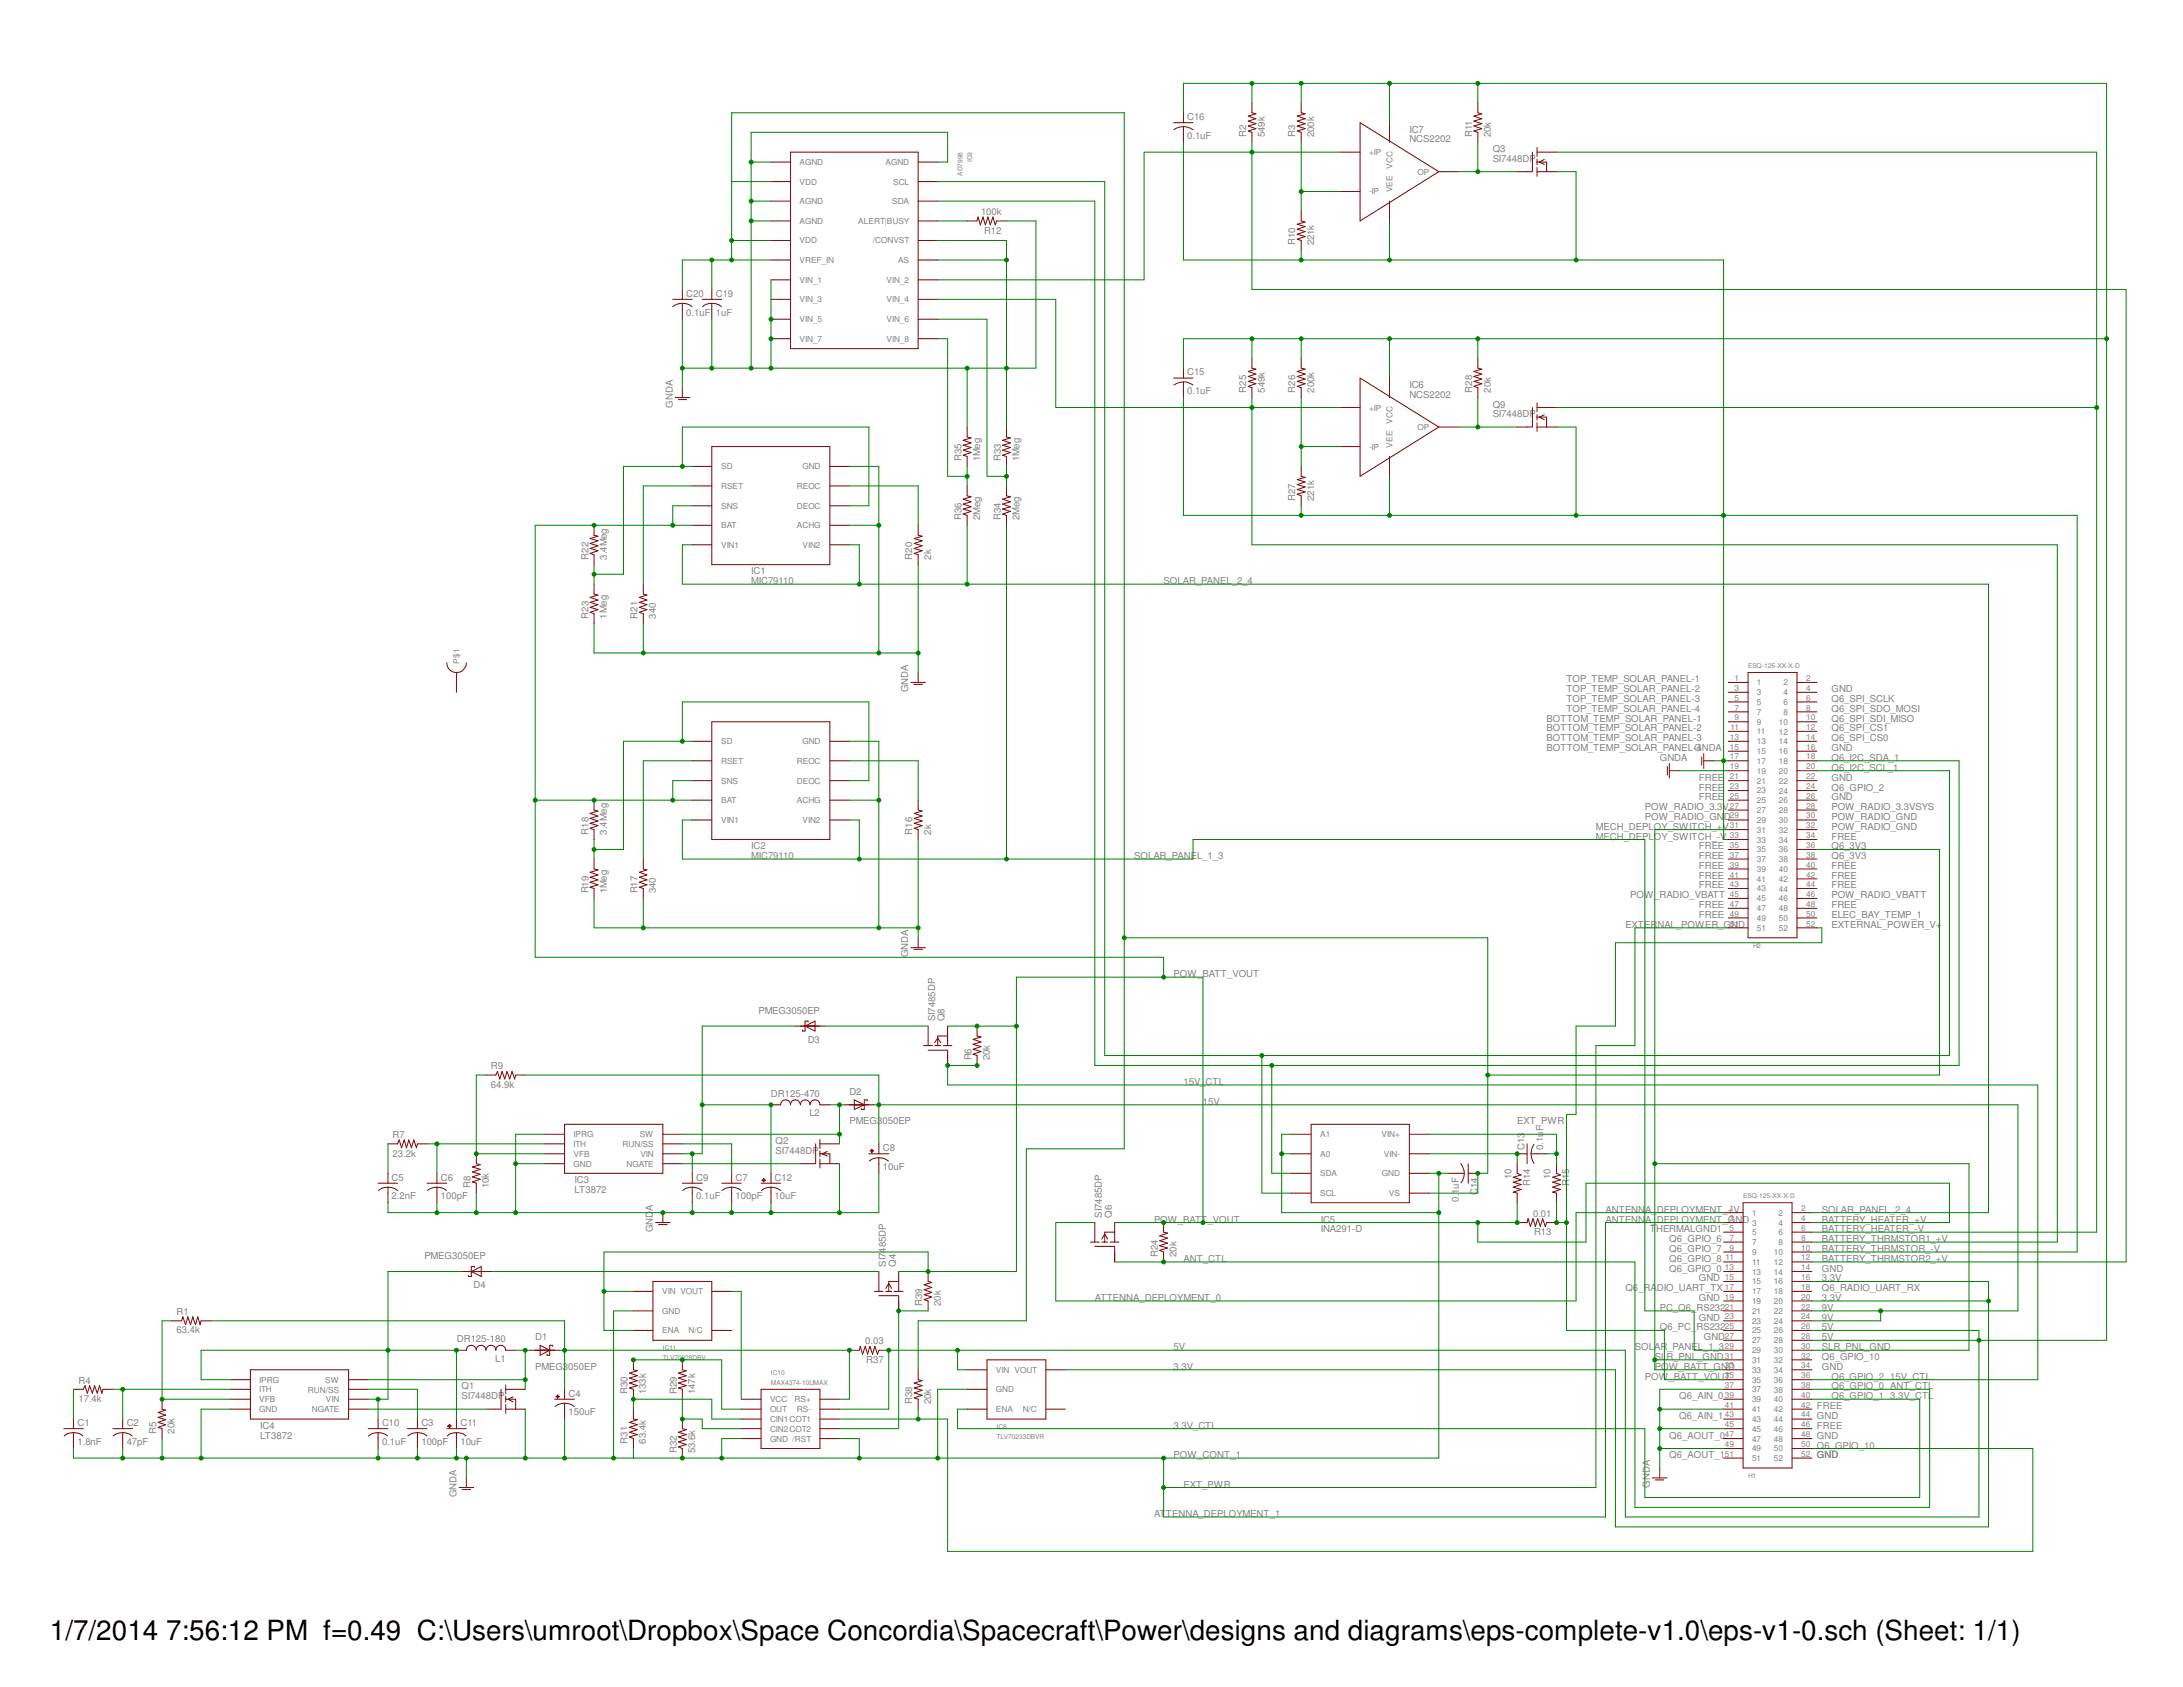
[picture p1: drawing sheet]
<svg xmlns="http://www.w3.org/2000/svg" width="279mm" height="216mm" viewBox="0 0 279 216" stroke-linecap="round" stroke-linejoin="round" font-family="sans-serif">
<defs><g id="words">
<text font-size="3.6" x="6.4" y="209.9">1/7/2014 7:56:12 PM f=0.49 C:\Users\umroot\Dropbox\Space Concordia\Spacecraft\Power\designs and diagrams\eps-complete-v1.0\eps-v1-0.sch (Sheet: 1/1)</text>
<g font-size="1.2" fill="#808080">
<text x="151.9" y="17.8">0.1uF</text>
<text x="151.9" y="15.4">C16</text>
<text x="159.5" y="17.6" transform="rotate(-90 159.5 17.6)">R2</text>
<text x="161.9" y="17.6" transform="rotate(-90 161.9 17.6)">549k</text>
<text x="165.8" y="17.6" transform="rotate(-90 165.8 17.6)">R3</text>
<text x="168.2" y="17.6" transform="rotate(-90 168.2 17.6)">200k</text>
<text x="180.4" y="17">IC7</text>
<text x="188.4" y="17.6" transform="rotate(-90 188.4 17.6)">R11</text>
<text x="190.8" y="17.6" transform="rotate(-90 190.8 17.6)">20k</text>
<text x="180.4" y="18.2">NCS2202</text>
<text x="191.1" y="20.7">SI7448DP</text>
<text x="191.1" y="19.5">Q3</text>
<text x="125.6" y="27.5">100k</text>
<text x="125.9" y="29.9">R12</text>
<text x="165.8" y="31.4" transform="rotate(-90 165.8 31.4)">R10</text>
<text x="168.2" y="31.4" transform="rotate(-90 168.2 31.4)">221k</text>
<text x="87.8" y="40.4">0.1uF 1uF</text>
<text x="87.8" y="38">C20</text>
<text x="91.6" y="38">C19</text>
<text x="86.1" y="52.2" transform="rotate(-90 86.1 52.2)">GNDA</text>
<text x="151.9" y="50.5">0.1uF</text>
<text x="151.9" y="48">C15</text>
<text x="159.5" y="50.2" transform="rotate(-90 159.5 50.2)">R25</text>
<text x="161.9" y="50.2" transform="rotate(-90 161.9 50.2)">549k</text>
<text x="165.8" y="50.2" transform="rotate(-90 165.8 50.2)">R26</text>
<text x="168.2" y="50.2" transform="rotate(-90 168.2 50.2)">200k</text>
<text x="180.4" y="50.9">NCS2202</text>
<text x="180.4" y="49.6">IC6</text>
<text x="188.4" y="50.2" transform="rotate(-90 188.4 50.2)">R28</text>
<text x="190.8" y="50.2" transform="rotate(-90 190.8 50.2)">20k</text>
<text x="191.1" y="53.4">SI7448DP</text>
<text x="191.1" y="52.2">Q9</text>
<text x="123.1" y="59.1" transform="rotate(-90 123.1 59.1)">R35</text>
<text x="125.4" y="59.1" transform="rotate(-90 125.4 59.1)">1Meg</text>
<text x="128.1" y="59.1" transform="rotate(-90 128.1 59.1)">R33</text>
<text x="130.5" y="59.1" transform="rotate(-90 130.5 59.1)">1Meg</text>
<text x="165.8" y="64.1" transform="rotate(-90 165.8 64.1)">R27</text>
<text x="168.2" y="64.1" transform="rotate(-90 168.2 64.1)">221k</text>
<text x="75.3" y="71.6" transform="rotate(-90 75.3 71.6)">R22</text>
<text x="77.7" y="71.6" transform="rotate(-90 77.7 71.6)">3.4Meg</text>
<text x="116.8" y="71.6" transform="rotate(-90 116.8 71.6)">R20</text>
<text x="119.2" y="71.6" transform="rotate(-90 119.2 71.6)">2k</text>
<text x="123.1" y="66.6" transform="rotate(-90 123.1 66.6)">R36</text>
<text x="125.4" y="66.6" transform="rotate(-90 125.4 66.6)">2Meg</text>
<text x="128.1" y="66.6" transform="rotate(-90 128.1 66.6)">R34</text>
<text x="130.5" y="66.6" transform="rotate(-90 130.5 66.6)">2Meg</text>
<text x="96.1" y="74.8">MIC79110</text>
<text x="96.1" y="73.5">IC1</text>
<text x="148.9" y="74.8">SOLAR_PANEL_2_4</text>
<text x="75.3" y="79.2" transform="rotate(-90 75.3 79.2)">R23</text>
<text x="77.7" y="79.2" transform="rotate(-90 77.7 79.2)">1Meg</text>
<text x="81.6" y="79.2" transform="rotate(-90 81.6 79.2)">R21</text>
<text x="83.9" y="79.2" transform="rotate(-90 83.9 79.2)">340</text>
<text x="116.2" y="88.6" transform="rotate(-90 116.2 88.6)">GNDA</text>
<text x="200.5" y="89.8">TOP_TEMP_SOLAR_PANEL-3</text>
<text x="200.5" y="88.6">TOP_TEMP_SOLAR_PANEL-2</text>
<text x="200.5" y="87.3">TOP_TEMP_SOLAR_PANEL-1</text>
<text x="234.4" y="89.8">Q6_SPI_SCLK</text>
<text x="234.4" y="88.6">GND</text>
<text x="198" y="92.4">BOTTOM_TEMP_SOLAR_PANEL-1</text>
<text x="198" y="93.6">BOTTOM_TEMP_SOLAR_PANEL-2</text>
<text x="198" y="94.9">BOTTOM_TEMP_SOLAR_PANEL-3</text>
<text x="200.5" y="91.1">TOP_TEMP_SOLAR_PANEL-4</text>
<text x="234.4" y="91.1">Q6_SPI_SDO_MOSI</text>
<text x="234.4" y="92.4">Q6_SPI_SDI_MISO</text>
<text x="234.4" y="93.6">Q6_SPI_CS1</text>
<text x="234.4" y="94.9">Q6_SPI_CS0</text>
<text x="198" y="96.1">BOTTOM_TEMP_SOLAR_PANEL-4</text>
<text x="212.4" y="97.4">GNDA</text>
<text x="216.8" y="96.1">GNDA</text>
<text x="217.4" y="99.9">FREE</text>
<text x="217.4" y="101.2">FREE</text>
<text x="234.4" y="97.4">Q6_I2C_SDA_1</text>
<text x="234.4" y="96.1">GND</text>
<text x="234.4" y="99.9">GND</text>
<text x="234.4" y="98.6">Q6_I2C_SCL_1</text>
<text x="234.4" y="101.2">Q6_GPIO_2</text>
<text x="75.3" y="106.8" transform="rotate(-90 75.3 106.8)">R18</text>
<text x="77.7" y="106.8" transform="rotate(-90 77.7 106.8)">3.4Meg</text>
<text x="116.8" y="106.8" transform="rotate(-90 116.8 106.8)">R16</text>
<text x="119.2" y="106.8" transform="rotate(-90 119.2 106.8)">2k</text>
<text x="204.3" y="107.4">MECH_DEPLOY_SWITCH_-V</text>
<text x="204.3" y="106.2">MECH_DEPLOY_SWITCH_+V</text>
<text x="210.5" y="103.7">POW_RADIO_3.3V</text>
<text x="210.5" y="104.9">POW_RADIO_GND</text>
<text x="217.4" y="102.4">FREE</text>
<text x="234.4" y="102.4">GND</text>
<text x="234.4" y="103.7">POW_RADIO_3.3VSYS</text>
<text x="234.4" y="104.9">POW_RADIO_GND</text>
<text x="234.4" y="106.2">POW_RADIO_GND</text>
<text x="234.4" y="107.4">FREE</text>
<text x="96.1" y="109.9">MIC79110</text>
<text x="96.1" y="108.7">IC2</text>
<text x="145.2" y="109.9">SOLAR_PANEL_1_3</text>
<text x="217.4" y="108.7">FREE</text>
<text x="217.4" y="109.9">FREE</text>
<text x="217.4" y="111.2">FREE</text>
<text x="217.4" y="112.5">FREE</text>
<text x="217.4" y="113.7">FREE</text>
<text x="234.4" y="108.7">Q6_3V3</text>
<text x="234.4" y="109.9">Q6_3V3</text>
<text x="234.4" y="113.7">FREE</text>
<text x="234.4" y="112.5">FREE</text>
<text x="234.4" y="111.2">FREE</text>
<text x="75.3" y="114.3" transform="rotate(-90 75.3 114.3)">R19</text>
<text x="77.7" y="114.3" transform="rotate(-90 77.7 114.3)">1Meg</text>
<text x="81.6" y="114.3" transform="rotate(-90 81.6 114.3)">R17</text>
<text x="83.9" y="114.3" transform="rotate(-90 83.9 114.3)">340</text>
<text x="208" y="118.7">EXTERNAL_POWER_GND</text>
<text x="208.7" y="115">POW_RADIO_VBATT</text>
<text x="217.4" y="116.2">FREE</text>
<text x="217.4" y="117.5">FREE</text>
<text x="234.4" y="115">POW_RADIO_VBATT</text>
<text x="234.4" y="117.5">ELEC_BAY_TEMP_1</text>
<text x="234.4" y="118.7">EXTERNAL_POWER_V+</text>
<text x="234.4" y="116.2">FREE</text>
<text x="116.2" y="122.5" transform="rotate(-90 116.2 122.5)">GNDA</text>
<text x="150.2" y="125.1">POW_BATT_VOUT</text>
<text x="97.1" y="129.7">PMEG3050EP</text>
<text x="119.7" y="130.7" transform="rotate(-90 119.7 130.7)">SI7485DP</text>
<text x="120.9" y="130.7" transform="rotate(-90 120.9 130.7)">Q8</text>
<text x="62.8" y="136.9">R9</text>
<text x="103.4" y="133.5">D3</text>
<text x="124.3" y="135.7" transform="rotate(-90 124.3 135.7)">R6</text>
<text x="126.7" y="135.7" transform="rotate(-90 126.7 135.7)">20k</text>
<text x="62.8" y="139.2">64.9k</text>
<text x="98.7" y="140.4">DR125-470</text>
<text x="103.6" y="142.9">L2</text>
<text x="108.7" y="143.9">PMEG3050EP</text>
<text x="108.7" y="140.1">D2</text>
<text x="151.5" y="138.9">15V_CTL</text>
<text x="154" y="141.4">15V</text>
<text x="194.2" y="143.9">EXT_PWR</text>
<text x="50.2" y="148">23.2k</text>
<text x="50.2" y="145.7">R7</text>
<text x="99.3" y="147.7">SI7448DP</text>
<text x="99.3" y="146.4">Q2</text>
<text x="113" y="149.7">10uF</text>
<text x="113" y="147.4">C8</text>
<text x="195.1" y="147.2" transform="rotate(-90 195.1 147.2)">C13</text>
<text x="197.5" y="147.2" transform="rotate(-90 197.5 147.2)">0.1uF</text>
<text x="50.1" y="153.5">2.2nF</text>
<text x="50.1" y="151.1">C5</text>
<text x="56.4" y="151.1">C6</text>
<text x="56.4" y="153.5">100pF</text>
<text x="60.2" y="152.1" transform="rotate(-90 60.2 152.1)">R8</text>
<text x="62.6" y="152.1" transform="rotate(-90 62.6 152.1)">10k</text>
<text x="73.5" y="151.4">IC3</text>
<text x="73.5" y="152.7">LT3872</text>
<text x="89.1" y="153.5">0.1uF</text>
<text x="89.1" y="151.1">C9</text>
<text x="94.1" y="153.5">100pF</text>
<text x="94.1" y="151.1">C7</text>
<text x="99.1" y="153.5">10uF</text>
<text x="99.1" y="151.1">C12</text>
<text x="141" y="155.8" transform="rotate(-90 141 155.8)">SI7485DP</text>
<text x="142.3" y="155.8" transform="rotate(-90 142.3 155.8)">Q6</text>
<text x="186.7" y="153.8" transform="rotate(-90 186.7 153.8)">0.1uF</text>
<text x="189.1" y="152.9" transform="rotate(-90 189.1 152.9)">C14</text>
<text x="193.5" y="150.9" transform="rotate(-90 193.5 150.9)">10</text>
<text x="195.8" y="151.8" transform="rotate(-90 195.8 151.8)">R14</text>
<text x="196.2" y="155.7">0.01</text>
<text x="198.5" y="150.9" transform="rotate(-90 198.5 150.9)">10</text>
<text x="200.8" y="151.8" transform="rotate(-90 200.8 151.8)">R15</text>
<text x="205.5" y="155.2">ANTENNA_DEPLOYMENT_+V</text>
<text x="233.2" y="155.2">SOLAR_PANEL_2_4</text>
<text x="54.3" y="161.1">PMEG3050EP</text>
<text x="83.6" y="157.7" transform="rotate(-90 83.6 157.7)">GNDA</text>
<text x="147.7" y="156.5">POW_BATT_VOUT</text>
<text x="148.2" y="160.9" transform="rotate(-90 148.2 160.9)">R24</text>
<text x="150.6" y="160.9" transform="rotate(-90 150.6 160.9)">20k</text>
<text x="151.5" y="161.5">ANT_CTL</text>
<text x="169" y="156.5">IC5</text>
<text x="169" y="157.7">INA291-D</text>
<text x="196.3" y="158.1">R13</text>
<text x="205.5" y="156.5">ANTENNA_DEPLOYMENT_GND</text>
<text x="211.2" y="157.7">THERMALGND1</text>
<text x="213.7" y="159">Q6_GPIO_6</text>
<text x="213.7" y="160.2">Q6_GPIO_7</text>
<text x="213.7" y="161.5">Q6_GPIO_8</text>
<text x="233.2" y="156.5">BATTERY_HEATER_+V</text>
<text x="233.2" y="157.7">BATTERY_HEATER_-V</text>
<text x="233.2" y="159">BATTERY_THRMSTOR1_+V</text>
<text x="233.2" y="160.2">BATTERY_THRMSTOR_-V</text>
<text x="233.2" y="161.5">BATTERY_THRMSTOR2_+V</text>
<text x="60.6" y="164.9">D4</text>
<text x="113.4" y="162.1" transform="rotate(-90 113.4 162.1)">SI7485DP</text>
<text x="114.6" y="162.1" transform="rotate(-90 114.6 162.1)">Q4</text>
<text x="118" y="167.1" transform="rotate(-90 118 167.1)">R39</text>
<text x="120.4" y="167.1" transform="rotate(-90 120.4 167.1)">20k</text>
<text x="140.1" y="166.5">ATTENNA_DEPLOYMENT_0</text>
<text x="208" y="165.3">Q6_RADIO_UART_TX</text>
<text x="212.4" y="167.8">PC_Q6_RS232</text>
<text x="213.7" y="162.7">Q6_GPIO_0</text>
<text x="217.4" y="164">GND</text>
<text x="217.4" y="166.5">GND</text>
<text x="233.2" y="165.3">Q6_RADIO_UART_RX</text>
<text x="233.2" y="164">3.3V</text>
<text x="233.2" y="166.5">3.3V</text>
<text x="233.2" y="167.8">9V</text>
<text x="233.2" y="162.7">GND</text>
<text x="22.6" y="170.6">63.4k</text>
<text x="22.6" y="168.3">R1</text>
<text x="58.5" y="171.8">DR125-180</text>
<text x="68.5" y="171.5">D1</text>
<text x="110.7" y="172">0.03</text>
<text x="150.2" y="172.8">5V</text>
<text x="209.3" y="172.8">SOLAR_PANEL_1_3</text>
<text x="212.4" y="170.3">Q6_PC_RS232</text>
<text x="217.4" y="169">GND</text>
<text x="218.1" y="171.5">GND</text>
<text x="233.2" y="171.5">5V</text>
<text x="233.2" y="170.3">5V</text>
<text x="233.2" y="169">9V</text>
<text x="233.2" y="172.8">SLR_PNL_GND</text>
<text x="10" y="179.5">17.4k</text>
<text x="10" y="177.1">R4</text>
<text x="59.1" y="179.1">SI7448DP</text>
<text x="59.1" y="177.8">Q1</text>
<text x="63.4" y="174.3">L1</text>
<text x="68.5" y="175.3">PMEG3050EP</text>
<text x="72.8" y="178.8">C4</text>
<text x="80.3" y="178.4" transform="rotate(-90 80.3 178.4)">R30</text>
<text x="82.7" y="178.4" transform="rotate(-90 82.7 178.4)">133k</text>
<text x="86.6" y="178.4" transform="rotate(-90 86.6 178.4)">R29</text>
<text x="89" y="178.4" transform="rotate(-90 89 178.4)">147k</text>
<text x="110.9" y="174.4">R37</text>
<text x="116.8" y="179.7" transform="rotate(-90 116.8 179.7)">R38</text>
<text x="119.2" y="179.7" transform="rotate(-90 119.2 179.7)">20k</text>
<text x="150.2" y="175.3">3.3V</text>
<text x="210.5" y="176.6">POW_BATT_VOUT</text>
<text x="211.8" y="175.3">POW_BATT_GND</text>
<text x="211.8" y="174">SLR_PNL_GND</text>
<text x="214.9" y="179.1">Q6_AIN_0</text>
<text x="233.2" y="174">Q6_GPIO_10</text>
<text x="233.2" y="175.3">GND</text>
<text x="234.4" y="177.8">Q6_GPIO_0 ANT_CTL</text>
<text x="234.4" y="179.1">Q6_GPIO_1</text>
<text x="234.4" y="176.6">Q6_GPIO_2</text>
<text x="241.9" y="179.1">3.3V_CTL</text>
<text x="241.9" y="176.6">15V_CTL</text>
<text x="9.9" y="184.9">1.8nF</text>
<text x="9.9" y="182.5">C1</text>
<text x="16.2" y="182.5">C2</text>
<text x="16.2" y="184.9">47pF</text>
<text x="20" y="183.5" transform="rotate(-90 20 183.5)">R5</text>
<text x="22.4" y="183.5" transform="rotate(-90 22.4 183.5)">20k</text>
<text x="33.3" y="182.8">IC4</text>
<text x="33.3" y="184.1">LT3872</text>
<text x="48.9" y="184.9">0.1uF</text>
<text x="48.9" y="182.5">C10</text>
<text x="53.9" y="184.9">100pF</text>
<text x="53.9" y="182.5">C3</text>
<text x="58.9" y="184.9">10uF</text>
<text x="58.9" y="182.5">C11</text>
<text x="72.8" y="181.1">150uF</text>
<text x="80.3" y="184.7" transform="rotate(-90 80.3 184.7)">R31</text>
<text x="82.7" y="184.7" transform="rotate(-90 82.7 184.7)">63.4k</text>
<text x="86.6" y="186" transform="rotate(-90 86.6 186)">R32</text>
<text x="89" y="186" transform="rotate(-90 89 186)">53.6k</text>
<text x="150.2" y="182.8">3.3V_CTL</text>
<text x="213.7" y="184.1">Q6_AOUT_0</text>
<text x="214.9" y="181.6">Q6_AIN_1</text>
<text x="232.5" y="185.4">Q6_GPIO_10</text>
<text x="232.5" y="182.8">FREE</text>
<text x="232.5" y="181.6">GND</text>
<text x="232.5" y="180.3">FREE</text>
<text x="232.5" y="184.1">GND</text>
<text x="58.4" y="191.6" transform="rotate(-90 58.4 191.6)">GNDA</text>
<text x="150.2" y="186.6">POW_CONT_1</text>
<text x="151.5" y="190.4">EXT_PWR</text>
<text x="211.2" y="190.4" transform="rotate(-90 211.2 190.4)">GNDA</text>
<text x="213.7" y="186.6">Q6_AOUT_1</text>
<text x="232.5" y="186.6">GND</text>
<text x="147.7" y="194.1">ATTENNA_DEPLOYMENT_1</text>
</g>
<g font-size="1.1" fill="#808080">
<text x="102.3" y="21.1">AGND</text>
<text x="102.3" y="23.6">VDD</text>
<text x="113.3" y="21.1">AGND</text>
<text x="114.3" y="23.6">SCL</text>
<text x="175.2" y="19.9">+IP</text>
<text x="178.2" y="21.6" transform="rotate(-90 178.2 21.6)">VCC</text>
<text x="181.4" y="22.4">OP</text>
<text x="102.3" y="26.1">AGND</text>
<text x="102.3" y="28.7">AGND</text>
<text x="109.9" y="28.7">ALERT|BUSY</text>
<text x="114.2" y="26.1">SDA</text>
<text x="175.2" y="24.9">-IP</text>
<text x="178.2" y="24.6" transform="rotate(-90 178.2 24.6)">VEE</text>
<text x="102.3" y="31.2">VDD</text>
<text x="102.3" y="33.7">VREF_IN</text>
<text x="111.7" y="31.2">/CONVST</text>
<text x="114.9" y="33.7">AS</text>
<text x="102.3" y="36.2">VIN_1</text>
<text x="102.3" y="38.7">VIN_3</text>
<text x="102.3" y="41.2">VIN_5</text>
<text x="113.5" y="41.2">VIN_6</text>
<text x="113.5" y="38.7">VIN_4</text>
<text x="113.5" y="36.2">VIN_2</text>
<text x="102.3" y="43.7">VIN_7</text>
<text x="113.5" y="43.7">VIN_8</text>
<text x="175.2" y="52.5">+IP</text>
<text x="175.2" y="57.5">-IP</text>
<text x="178.2" y="57.3" transform="rotate(-90 178.2 57.3)">VEE</text>
<text x="178.2" y="54.3" transform="rotate(-90 178.2 54.3)">VCC</text>
<text x="181.4" y="55">OP</text>
<text x="92.3" y="60.1">SD</text>
<text x="92.3" y="62.6">RSET</text>
<text x="92.3" y="65.1">SNS</text>
<text x="102" y="65.1">DEOC</text>
<text x="102" y="62.6">REOC</text>
<text x="102.7" y="60.1">GND</text>
<text x="92.3" y="67.6">BAT</text>
<text x="92.3" y="70.1">VIN1</text>
<text x="102" y="67.6">ACHG</text>
<text x="102.7" y="70.1">VIN2</text>
<text x="58.8" y="84.9" transform="rotate(-90 58.8 84.9)">P$1</text>
<text x="222" y="87.2">1</text>
<text x="222" y="88.4">3</text>
<text x="222" y="89.7">5</text>
<text x="224.9" y="87.7">1</text>
<text x="224.9" y="89">3</text>
<text x="228.3" y="87.7">2</text>
<text x="228.3" y="89">4</text>
<text x="231.2" y="87.2">2</text>
<text x="231.2" y="88.4">4</text>
<text x="231.2" y="89.7">6</text>
<text x="92.3" y="95.2">SD</text>
<text x="102.7" y="95.2">GND</text>
<text x="221.4" y="94.7">13</text>
<text x="221.4" y="96">15</text>
<text x="221.5" y="93.4">11</text>
<text x="222" y="90.9">7</text>
<text x="222" y="92.2">9</text>
<text x="224.9" y="90.2">5</text>
<text x="224.9" y="91.5">7</text>
<text x="224.9" y="92.8">9</text>
<text x="224.9" y="94">11</text>
<text x="224.9" y="95.2">13</text>
<text x="227.7" y="94">12</text>
<text x="227.7" y="95.2">14</text>
<text x="227.7" y="92.8">10</text>
<text x="228.3" y="90.2">6</text>
<text x="228.3" y="91.5">8</text>
<text x="231.2" y="90.9">8</text>
<text x="231.2" y="92.2">10</text>
<text x="231.2" y="93.4">12</text>
<text x="231.2" y="94.7">14</text>
<text x="231.2" y="96">16</text>
<text x="92.3" y="97.7">RSET</text>
<text x="92.3" y="100.3">SNS</text>
<text x="102" y="100.3">DEOC</text>
<text x="102" y="97.8">REOC</text>
<text x="221.4" y="97.2">17</text>
<text x="221.4" y="98.5">19</text>
<text x="221.4" y="99.7">21</text>
<text x="221.4" y="101">23</text>
<text x="224.9" y="96.5">15</text>
<text x="224.9" y="97.7">17</text>
<text x="224.9" y="99">19</text>
<text x="224.9" y="100.3">21</text>
<text x="224.9" y="101.5">23</text>
<text x="227.7" y="96.5">16</text>
<text x="227.7" y="97.8">18</text>
<text x="227.7" y="99">20</text>
<text x="227.7" y="100.3">22</text>
<text x="227.7" y="101.6">24</text>
<text x="231.2" y="97.2">18</text>
<text x="231.2" y="98.5">20</text>
<text x="231.2" y="99.7">22</text>
<text x="231.2" y="101">24</text>
<text x="92.3" y="102.8">BAT</text>
<text x="92.3" y="105.3">VIN1</text>
<text x="102" y="102.8">ACHG</text>
<text x="102.7" y="105.3">VIN2</text>
<text x="221.4" y="102.2">25</text>
<text x="221.4" y="103.5">27</text>
<text x="221.4" y="104.7">29</text>
<text x="221.4" y="106">31</text>
<text x="221.4" y="107.3">33</text>
<text x="224.9" y="102.8">25</text>
<text x="224.9" y="104.1">27</text>
<text x="224.9" y="105.3">29</text>
<text x="224.9" y="106.6">31</text>
<text x="224.9" y="107.8">33</text>
<text x="227.7" y="102.8">26</text>
<text x="227.7" y="104.1">28</text>
<text x="227.7" y="105.3">30</text>
<text x="227.7" y="106.6">32</text>
<text x="227.7" y="107.8">34</text>
<text x="231.2" y="102.2">26</text>
<text x="231.2" y="103.5">28</text>
<text x="231.2" y="104.7">30</text>
<text x="231.2" y="106">32</text>
<text x="231.2" y="107.3">34</text>
<text x="221.4" y="108.5">35</text>
<text x="221.4" y="109.8">37</text>
<text x="221.4" y="111">39</text>
<text x="221.4" y="112.3">41</text>
<text x="221.4" y="113.5">43</text>
<text x="224.9" y="109.1">35</text>
<text x="224.9" y="110.3">37</text>
<text x="224.9" y="111.6">39</text>
<text x="224.9" y="112.9">41</text>
<text x="227.7" y="109.1">36</text>
<text x="227.7" y="110.3">38</text>
<text x="227.7" y="111.6">40</text>
<text x="227.7" y="112.9">42</text>
<text x="231.2" y="108.5">36</text>
<text x="231.2" y="109.8">38</text>
<text x="231.2" y="111">40</text>
<text x="231.2" y="112.3">42</text>
<text x="231.2" y="113.5">44</text>
<text x="221.4" y="114.8">45</text>
<text x="221.4" y="116.1">47</text>
<text x="221.4" y="117.3">49</text>
<text x="221.4" y="118.6">51</text>
<text x="224.9" y="114.1">43</text>
<text x="224.9" y="115.4">45</text>
<text x="224.9" y="116.6">47</text>
<text x="224.9" y="117.9">49</text>
<text x="224.9" y="119.1">51</text>
<text x="227.7" y="114.1">44</text>
<text x="227.7" y="115.4">46</text>
<text x="227.7" y="116.6">48</text>
<text x="227.7" y="117.9">50</text>
<text x="227.7" y="119.1">52</text>
<text x="231.2" y="114.8">46</text>
<text x="231.2" y="116.1">48</text>
<text x="231.2" y="117.3">50</text>
<text x="231.2" y="118.6">52</text>
<text x="73.4" y="145.5">IPRG</text>
<text x="73.4" y="146.8">ITH</text>
<text x="73.4" y="148">VFB</text>
<text x="73.4" y="149.3">GND</text>
<text x="79.7" y="146.8">RUN/SS</text>
<text x="80.2" y="149.3">NGATE</text>
<text x="81.9" y="145.5">SW</text>
<text x="82" y="148">VIN</text>
<text x="169" y="145.5">A1</text>
<text x="169" y="148">A0</text>
<text x="176.8" y="145.5">VIN+</text>
<text x="177.1" y="148">VIN-</text>
<text x="169" y="150.5">SDA</text>
<text x="169" y="153.1">SCL</text>
<text x="176.9" y="150.5">GND</text>
<text x="177.8" y="153.1">VS</text>
<text x="221.4" y="155">1</text>
<text x="224.2" y="155.6">1</text>
<text x="227.6" y="155.6">2</text>
<text x="230.5" y="155">2</text>
<text x="220.9" y="161.3">11</text>
<text x="221.4" y="156.3">3</text>
<text x="221.4" y="157.5">5</text>
<text x="221.4" y="158.8">7</text>
<text x="221.4" y="160.1">9</text>
<text x="224.2" y="156.8">3</text>
<text x="224.2" y="158.1">5</text>
<text x="224.2" y="159.3">7</text>
<text x="224.2" y="160.6">9</text>
<text x="224.2" y="161.8">11</text>
<text x="227" y="161.9">12</text>
<text x="227" y="160.6">10</text>
<text x="227.6" y="156.8">4</text>
<text x="227.6" y="158.1">6</text>
<text x="227.6" y="159.3">8</text>
<text x="230.5" y="156.3">4</text>
<text x="230.5" y="157.5">6</text>
<text x="230.5" y="158.8">8</text>
<text x="230.5" y="160.1">10</text>
<text x="230.5" y="161.3">12</text>
<text x="84.8" y="165.7">VIN VOUT</text>
<text x="220.8" y="162.6">13</text>
<text x="220.8" y="163.8">15</text>
<text x="220.8" y="165.1">17</text>
<text x="220.8" y="166.3">19</text>
<text x="220.8" y="167.6">21</text>
<text x="224.2" y="163.1">13</text>
<text x="224.2" y="164.4">15</text>
<text x="224.2" y="165.7">17</text>
<text x="224.2" y="166.9">19</text>
<text x="227" y="163.1">14</text>
<text x="227" y="164.4">16</text>
<text x="227" y="165.7">18</text>
<text x="227" y="166.9">20</text>
<text x="230.5" y="162.6">14</text>
<text x="230.5" y="163.8">16</text>
<text x="230.5" y="165.1">18</text>
<text x="230.5" y="166.3">20</text>
<text x="230.5" y="167.6">22</text>
<text x="84.8" y="168.1">GND</text>
<text x="84.8" y="170.6">ENA</text>
<text x="88.1" y="170.6">N/C</text>
<text x="220.8" y="168.9">23</text>
<text x="220.8" y="170.1">25</text>
<text x="220.8" y="171.4">27</text>
<text x="220.8" y="172.6">29</text>
<text x="220.8" y="173.9">31</text>
<text x="224.2" y="168.1">21</text>
<text x="224.2" y="169.4">23</text>
<text x="224.2" y="170.6">25</text>
<text x="224.2" y="171.9">27</text>
<text x="224.2" y="173.2">29</text>
<text x="227" y="168.1">22</text>
<text x="227" y="169.4">24</text>
<text x="227" y="170.6">26</text>
<text x="227" y="171.9">28</text>
<text x="227" y="173.2">30</text>
<text x="230.5" y="168.9">24</text>
<text x="230.5" y="170.1">26</text>
<text x="230.5" y="171.4">28</text>
<text x="230.5" y="172.6">30</text>
<text x="230.5" y="173.9">32</text>
<text x="33.2" y="177">IPRG</text>
<text x="33.2" y="178.2">ITH</text>
<text x="33.2" y="179.5">VFB</text>
<text x="39.4" y="178.2">RUN/SS</text>
<text x="41.6" y="177">SW</text>
<text x="41.7" y="179.5">VIN</text>
<text x="98.6" y="179.5">VCC</text>
<text x="101.7" y="179.5">RS+</text>
<text x="127.5" y="175.7">VIN VOUT</text>
<text x="127.5" y="178.2">GND</text>
<text x="220.8" y="175.1">33</text>
<text x="220.8" y="176.4">35</text>
<text x="220.8" y="177.6">37</text>
<text x="220.8" y="178.9">39</text>
<text x="224.2" y="174.4">31</text>
<text x="224.2" y="175.7">33</text>
<text x="224.2" y="177">35</text>
<text x="224.2" y="178.2">37</text>
<text x="224.2" y="179.5">39</text>
<text x="227" y="174.5">32</text>
<text x="227" y="175.7">34</text>
<text x="227" y="177">36</text>
<text x="227" y="178.2">38</text>
<text x="227" y="179.5">40</text>
<text x="230.5" y="175.1">34</text>
<text x="230.5" y="176.4">36</text>
<text x="230.5" y="177.6">38</text>
<text x="230.5" y="178.9">40</text>
<text x="33.2" y="180.7">GND</text>
<text x="39.9" y="180.7">NGATE</text>
<text x="98.6" y="181.9">CIN1COT1</text>
<text x="98.6" y="180.7">OUT</text>
<text x="98.6" y="183.2">CIN2COT2</text>
<text x="98.6" y="184.5">GND /RST</text>
<text x="102" y="180.7">RS-</text>
<text x="127.5" y="180.7">ENA</text>
<text x="130.9" y="180.7">N/C</text>
<text x="220.8" y="180.2">41</text>
<text x="220.8" y="181.4">43</text>
<text x="220.8" y="182.7">45</text>
<text x="220.8" y="183.9">47</text>
<text x="220.8" y="185.2">49</text>
<text x="224.2" y="180.7">41</text>
<text x="224.2" y="181.9">43</text>
<text x="224.2" y="183.2">45</text>
<text x="224.2" y="184.5">47</text>
<text x="224.2" y="185.8">49</text>
<text x="227" y="180.7">42</text>
<text x="227" y="182">44</text>
<text x="227" y="183.2">46</text>
<text x="227" y="184.5">48</text>
<text x="227" y="185.8">50</text>
<text x="230.5" y="180.2">42</text>
<text x="230.5" y="181.4">44</text>
<text x="230.5" y="182.7">46</text>
<text x="230.5" y="183.9">48</text>
<text x="230.5" y="185.2">50</text>
<text x="220.8" y="186.4">51</text>
<text x="224.2" y="187">51</text>
<text x="227" y="187">52</text>
<text x="230.5" y="186.4">52</text>
</g>
<g font-size=".8" fill="#808080">
<text x="123.2" y="22.5" transform="rotate(-90 123.2 22.5)">AD7998</text>
<text x="124.4" y="20.8" transform="rotate(-90 124.4 20.8)">IC9</text>
<text x="223.7" y="85.4">ESQ-125-XX-X-D</text>
<text x="224.4" y="121.3">H2</text>
<text x="223.1" y="153.3">ESQ-125-XX-X-D</text>
<text x="84.8" y="172.8">IC11</text>
<text x="84.8" y="174">TLV70228DBV</text>
<text x="98.7" y="175.9">IC10</text>
<text x="98.7" y="177.2">MAX4374-10UMAX</text>
<text x="127.6" y="184.1">TLV70233DBVR</text>
<text x="127.6" y="182.8">IC8</text>
<text x="223.7" y="189.1">H1</text>
</g>
</g></defs>
<g fill="none" stroke="#800000" stroke-width=".13">
<path d="M88.6 59.7h2.5M91.1 57.1h15.1v15.2h-15.1zM106.2 59.7h2.5M76 67.2v1.3l.5 .1-1 .3 1 .3-1 .4 1 .2-1 .4 1 .3-1 .3 .5 .2v1.3M76 74.8v1.2l.5 .2-1 .3 1 .3-1 .3 1 .3-1 .3 1 .3-1 .4 .5 .1v1.3M82.3 74.8v1.2l.5 .2-1 .3 1 .3-1 .3 1 .3-1 .3 1 .3-1 .4 .5 .1v1.3M88.6 62.2h2.5M88.6 64.7h2.5M88.6 67.2h2.5M88.6 69.7h2.5M106.2 62.2h2.5M106.2 64.7h2.5"/>
<path d="M106.2 67.2h2.5M106.2 69.7h2.5M117.5 67.2v1.3l.5 .1-1 .3 1 .3-1 .4 1 .2-1 .4 1 .3-1 .3 .5 .2v1.3M88.6 94.9h2.5M88.6 97.4h2.5M88.6 99.9h2.5M91.1 92.4h15.1v15h-15.1zM106.2 94.9h2.5M106.2 97.4h2.5M106.2 99.9h2.5M116.6 87.3h1.8M117 87.6h1.1"/>
<path d="M117.5 86.1v1.2M76 102.4v1.3l.5 .1-1 .3 1 .3-1 .3 1 .4-1 .3 1 .3-1 .3 .5 .2v1.2M76 109.9v1.3l.5 .1-1 .3 1 .4-1 .3 1 .3-1 .3 1 .3-1 .3 .5 .2v1.3M82.3 109.9v1.3l.5 .1-1 .3 1 .4-1 .3 1 .3-1 .3 1 .3-1 .3 .5 .2v1.3M88.6 102.4h2.5M88.6 104.9h2.5M106.2 102.4h2.5M106.2 104.9h2.5M117.5 102.4v1.3l.5 .1-1 .3 1 .3-1 .3 1 .4-1 .3 1 .3-1 .3 .5 .2v1.2M62.2 137.6h1.3l.2-.5 .3 1 .3-1 .3 1 .3-1 .3 1 .3-1 .4 1 .1-.5h1.2M116.6 121.3h1.8M117 121.5h1.1"/>
<path d="M117.5 120v1.3M49.7 146.4h1.2l.2-.5 .3 1 .3-1 .3 1 .3-1 .4 1 .3-1 .3 1 .1-.5h1.3M61 147.7v1.2l.5 .2-1 .3 1 .2-1 .4 1 .3-1 .3 1 .3-1 .4 .5 .1v1.3M148.9 156.5v1.2l.5 .1-1 .4 1 .3-1 .3 1 .3-1 .3 1 .3-1 .3 .5 .2v1.3M9.4 177.8h1.3l.2-.5 .3 1 .3-1 .3 1 .3-1 .3 1 .3-1 .3 1 .2-.5h1.2M20.7 179.1v1.2l.5 .2-1 .3 1 .3-1 .3 1 .3-1 .3 1 .3-1 .4 .5 .1v1.3M22 169h1.2l.2-.5 .3 1 .3-1 .4 1 .3-1 .3 1 .3-1 .3 1 .1-.5h1.3M71 179.1h2.5M72.3 179.6l.8 .1 .4 .3M72.3 179.6l-.9 .1-.4 .3M72.3 179.6v.7M8.2 182.8h2.5"/>
<path d="M9.4 183.3l.9 .2 .3 .3M9.4 183.3l-.8 .2-.4 .3M9.4 181.6v1.2M9.4 183.3v2.1M14.4 182.8h2.6M15.7 183.3l.9 .2 .3 .3M15.7 183.3l-.8 .2-.4 .3M15.7 181.6v1.2M15.7 183.3v2.1M52.2 182.8h2.5M53.4 183.3l.9 .2 .4 .3M53.4 183.3l-.8 .2-.4 .3"/>
<path d="M53.4 181.6v1.2M53.4 183.3v2.1M58.8 190.4h1.8M59.1 190.6h1.1M59.7 189.1v1.3"/>
</g>
<path d="M71.2 178.7h.4v.1h-.4z" fill-rule="evenodd" fill="#800000"/>
<path d="M71.2 178.7h.4v.1h-.4z" fill="none" stroke="#800000" stroke-width=".13"/>
<path d="M71.3 178.5h.1v.4h-.1z" fill-rule="evenodd" fill="#800000"/>
<g fill="none" stroke="#800000" stroke-width=".13">
<path d="M48.4 151.4h2.5M49.7 151.9l.8 .2 .4 .3M49.7 151.9l-.9 .2-.4 .3M49.7 150.2v1.2M49.7 151.9v2M54.7 151.4h2.5M55.9 151.9l.9 .2 .3 .3M55.9 151.9l-.8 .2-.4 .3M55.9 150.2v1.2M55.9 151.9v2M92.4 151.4h2.5M93.6 151.9l.9 .2 .4 .3"/>
<path d="M93.6 151.9l-.8 .2-.4 .3M93.6 150.2v1.2M93.6 151.9v2M102.4 148.9h2M104.4 146.4v2.5M104.9 148.9h2.5M104.9 145.8v1.2M104.9 147.3v.7M104.9 148.3v1.2M104.9 147.7h1.3v1.2M104.9 146.4h2.5M105.9 147.4l-.7 .3 .7 .3"/>
<path d="M111.2 147.7h2.5M112.5 148.2l.8 .1 .4 .3M112.5 148.2l-.9 .1-.3 .3M112.5 148.2v.7M64.1 177.8v2.5h-1.9M64.7 177.2v1.2M64.7 178.7v.8M64.7 179.7v1.2M64.7 179.1h1.3v1.2M64.7 177.8h2.5M65.7 178.8l-.7 .3 .7 .3M71.3 178.5h.1v.4h-.1z"/>
<path d="M72.3 177.8v1.3M64.7 180.3h2.5M72.3 180.3v1.3"/>
</g>
<path d="M111.4 147.2h.4v.1h-.4z" fill-rule="evenodd" fill="#800000"/>
<path d="M111.4 147.2h.4v.1h-.4z" fill="none" stroke="#800000" stroke-width=".13"/>
<path d="M111.5 147.1h.1v.4h-.1z" fill-rule="evenodd" fill="#800000"/>
<g fill="none" stroke="#800000" stroke-width=".13">
<path d="M118.2 133.8h1.1M118.8 134.4h2.5M118.8 131.3v2.5M119.6 133.8h.8M119.6 133.4l.4-.6 .4 .6M120.7 133.8h1.1M121.3 131.3v2.5M121.3 134.5v1.9M121.3 132.6h-1.3v1.2M125.1 131.3v1.3l.5 .1-1.1 .3 1.1 .3-1.1 .3 1.1 .3-1.1 .4 1.1 .3-1.1 .3 .6 .2v1.3M87.3 151.4h2.6M88.6 151.9l.9 .2 .3 .3"/>
<path d="M88.6 151.9l-.8 .2-.4 .3M88.6 150.2v1.2M88.6 151.9v2M98.7 141.4h1.2a.63 .63 0 0 1 .6-.6 .63 .63 0 0 1 .7 .6 .63 .63 0 0 1 .6-.6 .63 .63 0 0 1 .6 .6 .61 .61 0 0 1 .7-.6 .61 .61 0 0 1 .6 .6 .63 .63 0 0 1 .6-.6 .63 .63 0 0 1 .6 .6h1.3M111.5 147.1h.1v.4h-.1zM112.5 146.4v1.3M112.5 148.9v1.3M139.6 159h1.1M140.1 159.5h2.6M140.1 156.5v2.5M141 159h.8M141 158.6l.4-.7 .4 .7"/>
<path d="M142.1 159h1.1M142.7 156.5v2.5M142.7 159.6v1.9M142.7 157.7h-1.3v1.3M58.4 172.8h1.3a.63 .63 0 0 1 .6-.6 .63 .63 0 0 1 .7 .6 .61 .61 0 0 1 .6-.6 .61 .61 0 0 1 .6 .6 .63 .63 0 0 1 .6-.6 .63 .63 0 0 1 .7 .6 .63 .63 0 0 1 .6-.6 .63 .63 0 0 1 .6 .6h1.3M47.1 182.8h2.6M48.4 183.3l.8 .2 .4 .3M48.4 183.3l-.9 .2-.3 .3M48.4 181.6v1.2M48.4 183.3v2.1M57.2 182.8h2.5M58.4 183.3l.9 .2 .3 .3"/>
<path d="M58.4 183.3l-.8 .2-.4 .3M58.4 183.3v.8"/>
</g>
<path d="M57.3 182.5h.4h-.4z" fill-rule="evenodd" fill="#800000"/>
<path d="M57.3 182.5h.4h-.4z" fill="none" stroke="#800000" stroke-width=".13"/>
<path d="M57.5 182.3h.1v.4h-.1z" fill-rule="evenodd" fill="#800000"/>
<path d="M97.4 151.4h2.5M98.7 151.9l.8 .2 .4 .3M98.7 151.9l-.9 .2-.3 .3M98.7 151.9v.8M57.5 182.3h.1v.4h-.1zM58.4 181.6v1.2M58.4 184.1v1.3" fill="none" stroke="#800000" stroke-width=".13"/>
<path d="M97.5 151h.5v.1h-.5z" fill-rule="evenodd" fill="#800000"/>
<path d="M97.5 151h.5v.1h-.5z" fill="none" stroke="#800000" stroke-width=".13"/>
<path d="M97.7 150.8h.1v.5h-.1z" fill-rule="evenodd" fill="#800000"/>
<g fill="none" stroke="#800000" stroke-width=".13">
<path d="M101.2 19.5h16.3v25.1h-16.3zM150.2 15.7h2.5M150.2 16.6l.8-.3 .5-.1v2M151.5 16.2l.8 .2 .4 .2M151.5 14.4v1.3M160.2 13.2v1.2l.5 .2-.9 .3 .9 .3-.9 .3 .9 .3-.9 .3 .9 .4-.9 .3 .4 .1v1.3M166.5 13.2v1.2l.5 .2-1 .3 1 .3-1 .3 1 .3-1 .3 1 .4-1 .3 .5 .1v1.3M171.6 19.5h2.5M174.1 15.7l10 6.3-10 6.3zM177.8 15.7v2.5M189.1 13.2v1.2l.6 .2-1.1 .3 1.1 .3-1.1 .3 1.1 .3-1.1 .3 1.1 .4-1.1 .3 .5 .1v1.3M196.1 19.5v2.5"/>
<path d="M196.7 18.9v1.1M196.7 19.5h2.5M86.1 38.3h2.5M87.3 38.8l.9 .2 .4 .2M87.3 38.8l-.8 .2-.4 .2M87.3 37v1.3M87.3 38.8v2.1M89.9 38.3h2.5M91.1 38.8l.9 .2 .3 .2M91.1 38.8l-.8 .2-.4 .2M91.1 37v1.3M91.1 38.8v2.1"/>
<path d="M98.7 20.7h2.5M98.7 23.2h2.5M98.7 25.7h2.5M98.7 28.3h2.5M98.7 30.8h2.5M98.7 33.3h2.5M98.7 35.8h2.5M98.7 38.3h2.5M117.5 20.7h2.5M117.5 23.2h2.5M117.5 25.7h2.5M117.5 28.3h2.5"/>
<path d="M117.5 30.8h2.5M117.5 33.3h2.5M117.5 35.8h2.5M117.5 38.3h2.5M123.8 28.3h1.3l.1-.5 .3 1 .3-1 .3 1 .3-1 .3 1 .4-1 .3 1 .2-.5h1.2M166.5 27v1.3l.5 .1-1 .3 1 .3-1 .3 1 .3-1 .4 1 .3-1 .3 .5 .2v1.2M171.6 24.5h2.5M177.8 25.7v2.6M184.1 22h2.5M194.2 22h1.9M196.7 20.4v.7M196.7 21.4v1.2"/>
<path d="M196.7 20.7h1.3v1.3M196.7 22h2.5M197.7 20.4l-.7 .3 .7 .3M86.4 50.9h1.9M86.8 51.1h1.1M87.3 49.6v1.3M98.7 40.9h2.5M98.7 43.3h2.5M117.5 40.9h2.5M117.5 43.3h2.5M123.8 54.7v1.2l.5 .1-1 .3 1 .4-1 .3 1 .3-1 .3 1 .3-1 .4 .5 .1v1.3M128.8 54.7v1.2l.5 .1-1 .3 1 .4-1 .3 1 .3-1 .3 1 .3-1 .4 .5 .1v1.3"/>
<path d="M150.2 48.4h2.5M150.2 49.3l.8-.4h.5v2M151.5 48.9h.4l.8 .4M151.5 47.1v1.3M160.2 45.8v1.3l.5 .1-.9 .3 .9 .4-.9 .3 .9 .3-.9 .3 .9 .3-.9 .3 .4 .2v1.3M166.5 45.8v1.3l.5 .1-1 .3 1 .4-1 .3 1 .3-1 .3 1 .3-1 .3 .5 .2v1.3M166.5 59.7v1.3l.5 .1-1 .3 1 .3-1 .3 1 .3-1 .4 1 .2-1 .3 .5 .3v1.2M171.6 52.2h2.5M171.6 57.1h2.5M174.1 48.4l10 6.3-10 6.3zM177.8 48.4v2.5M177.8 58.4v2.6"/>
<path d="M184.1 54.7h2.5M189.1 45.8v1.3l.6 .1-1.1 .3 1.1 .4-1.1 .3 1.1 .3-1.1 .3 1.1 .3-1.1 .3 .5 .2v1.3M194.2 54.7h1.9M196.1 52.2v2.5M196.7 54.7h2.5M196.7 52.2h2.5M196.7 51.6v1.1M196.7 53v.8M196.7 54.1v1.1M196.7 53.4h1.3v1.3M197.7 53.1l-.7 .3 .7 .3M123.8 62.2v1.3l.5 .1-1 .3 1 .3-1 .3 1 .4-1 .3 1 .2-1 .4 .5 .2v1.2"/>
<path d="M128.8 62.2v1.3l.5 .1-1 .3 1 .3-1 .3 1 .4-1 .3 1 .2-1 .4 .5 .2v1.2M57.2 84.8a1.25 1.25 0 0 0 1.2 1.3 1.25 1.25 0 0 0 1.3-1.3M58.4 86.1v2.5M213.4 98.1v1.1M213.7 97.7v1.9M213.7 98.6h1.2M217.8 96.9v1M218.1 96.4v1.9M218.1 97.4h1.2M221.2 97.4h2.5M221.2 98.6h2.5M221.2 87.3h2.5"/>
<path d="M221.2 88.6h2.5M221.2 89.8h2.5M221.2 91.1h2.5M221.2 92.4h2.5M221.2 93.6h2.5M221.2 94.9h2.5M221.2 96.1h2.5M221.2 99.9h2.5M223.7 86.1h6.3v33.9h-6.3zM230 97.4h2.5M230 98.6h2.5M230 87.3h2.5"/>
<path d="M230 88.6h2.5M230 89.8h2.5M230 91.1h2.5M230 92.4h2.5M230 93.6h2.5M230 94.9h2.5M230 96.1h2.5M230 99.9h2.5M221.2 101.2h2.5M221.2 102.4h2.5M221.2 103.7h2.5M221.2 104.9h2.5"/>
<path d="M221.2 106.2h2.5M221.2 107.4h2.5M221.2 108.7h2.5M221.2 109.9h2.5M221.2 111.2h2.5M221.2 112.5h2.5M221.2 113.7h2.5M221.2 115h2.5M221.2 116.2h2.5M221.2 117.5h2.5M221.2 118.7h2.5M230 101.2h2.5"/>
<path d="M230 102.4h2.5M230 103.7h2.5M230 104.9h2.5M230 106.2h2.5M230 107.4h2.5M230 108.7h2.5M230 109.9h2.5M230 111.2h2.5M230 112.5h2.5M230 113.7h2.5M230 115h2.5M230 116.2h2.5"/>
<path d="M230 117.5h2.5M230 118.7h2.5M101.8 131.3h3.8M103 131.3l1.3-.6v1.3zM103.4 130.8v-.1h-.4v1.3h-.3v-.2M69.8 145.2h2.5M69.8 146.4h2.5M69.8 147.7h2.5M69.8 148.9h2.5M72.3 143.9h12.5v6.3h-12.5zM83.9 156.5h1.9M84.3 156.7h1.1"/>
<path d="M84.8 155.2v1.3M84.8 145.2h2.5M84.8 146.4h2.5M84.8 147.7h2.5M84.8 148.9h2.5M97.7 150.8h.1v.5h-.1zM98.7 150.2v1.2M98.7 152.7v1.2M108.1 141.4h3.7M109.3 140.8l1.3 .6-1.3 .6zM111 140.9v-.1h-.4v1.2h-.4v-.1M165.3 150.2h2.5"/>
<path d="M165.3 145.2h2.5M165.3 147.7h2.5M165.3 152.7h2.5M167.8 143.9h12.6v10h-12.6zM180.4 150.2h2.5M180.4 145.2h2.5M180.4 147.7h2.5M180.4 152.7h2.5M185.4 150.2h2M187 148.9l.4 .8v.5M187.4 150.2v.4l-.4 .8M187.9 150.2h1.2"/>
<path d="M187.9 148.9v2.5M194.2 147.7h1.3M194.2 156.5h1.3l.1-.5 .3 1 .3-1 .3 1 .3-1 .3 1 .3-1 .4 1 .2-.5h1.2M194.2 148.9v1.3l.5 .2-1 .3 1 .3-1 .3 1 .3-1 .3 1 .3-1 .4 .5 .1v1.2M195.5 146.4v2.5M196 147.7l.1 .8 .2 .4M196 147.7h2M196.3 146.4l-.2 .4-.1 .9M199.2 148.9v1.3l.5 .2-1 .3 1 .3-1 .3 1 .3-1 .3 1 .3-1 .4 .5 .1v1.2M220.6 155.2h2.5M220.6 156.5h2.5M220.6 157.7h2.5"/>
<path d="M220.6 159h2.5M223.1 153.9h6.3v34h-6.3zM229.4 155.2h2.5M229.4 156.5h2.5M229.4 157.7h2.5M229.4 159h2.5M29.5 176.6h2.5M29.5 177.8h2.5M29.5 179.1h2.5M32 175.3h12.6v6.3h-12.6zM44.6 176.6h2.5M44.6 177.8h2.5"/>
<path d="M44.6 179.1h2.5M59.1 162.7h3.7M60.3 162.7l1.3-.6v1.3zM60.7 162.2v-.1h-.4v1.3h-.4v-.2M67.9 172.8h3.7M69.1 172.2l1.3 .6-1.3 .6zM70.7 172.3v-.1h-.3v1.2h-.4v-.1M81.1 165.3h2.5M81.1 167.8h2.5M81.1 170.3h2.5M81.1 174v1.3l.5 .1-1 .3 1 .4-1 .3 1 .3-1 .3 1 .3-1 .3 .5 .2v1.3M83.6 164h7.5v7.5h-7.5z"/>
<path d="M87.3 174v1.3l.5 .1-1 .3 1 .4-1 .3 1 .3-1 .3 1 .3-1 .3 .5 .2v1.3M91.1 165.3h2.5M91.1 170.3h2.5M94.9 179.1h2.5M97.4 177.8h7.5v7.6h-7.5zM104.9 179.1h2.5M108.7 172.8h1.3l.1-.5 .3 1 .3-1 .3 1 .3-1 .4 1 .3-1 .3 1 .2-.5h1.2M111.9 165.3h1.1M112.5 165.8h2.5M112.5 162.7v2.6M113.4 165.3h.7M113.4 164.9l.3-.6 .4 .6"/>
<path d="M114.4 165.3h1.2M115 164h-1.3v1.3M115 162.7v2.6M115 165.9v1.9M117.5 175.3v1.3l.5 .1-1 .3 1 .3-1 .3 1 .3-1 .4 1 .3-1 .3 .5 .2v1.2M118.8 162.7v1.3l.5 .1-1 .3 1 .4-1 .3 1 .3-1 .3 1 .3-1 .3 .5 .2v1.3M123.8 175.3h2.5M123.8 177.8h2.5M126.3 174h7.6v7.6h-7.6zM133.9 175.3h2.5M220.6 162.7h2.5M220.6 172.8h2.5"/>
<path d="M220.6 175.3h2.5M220.6 176.6h2.5M220.6 177.8h2.5M220.6 179.1h2.5M220.6 160.2h2.5M220.6 161.5h2.5M220.6 164h2.5M220.6 165.3h2.5M220.6 166.5h2.5M220.6 167.8h2.5M220.6 169h2.5M220.6 170.3h2.5"/>
<path d="M220.6 171.5h2.5M220.6 174h2.5M229.4 162.7h2.5M229.4 172.8h2.5M229.4 175.3h2.5M229.4 176.6h2.5M229.4 177.8h2.5M229.4 179.1h2.5M229.4 160.2h2.5M229.4 161.5h2.5M229.4 164h2.5M229.4 165.3h2.5"/>
<path d="M229.4 166.5h2.5M229.4 167.8h2.5M229.4 169h2.5M229.4 170.3h2.5M229.4 171.5h2.5M229.4 174h2.5M29.5 180.3h2.5M44.6 180.3h2.5M81.1 180.3v1.3l.5 .1-1 .3 1 .3-1 .4 1 .3-1 .3 1 .3-1 .3 .5 .2v1.3M87.3 181.6v1.2l.5 .2-1 .3 1 .3-1 .3 1 .3-1 .3 1 .4-1 .3 .5 .2v1.2M94.9 181.6h2.5M94.9 180.3h2.5"/>
<path d="M94.9 182.8h2.5M94.9 184.1h2.5M104.9 181.6h2.5M104.9 180.3h2.5M104.9 182.8h2.5M104.9 184.1h2.5M123.8 180.3h2.5M133.9 180.3h2.5M211.5 189.1h1.9M211.9 189.4h1M212.4 187.9v1.2M220.6 181.6h2.5"/>
<path d="M220.6 180.3h2.5M220.6 182.8h2.5M220.6 184.1h2.5M220.6 185.4h2.5M220.6 186.6h2.5M229.4 181.6h2.5M229.4 180.3h2.5M229.4 182.8h2.5M229.4 184.1h2.5M229.4 185.4h2.5M229.4 186.6h2.5"/>
</g>
<path d="M22 169h-1.3v10.1h8.8M47.1 180.3h15.1" fill="none" stroke="#008000" stroke-width=".13"/>
<circle cx="20.7" cy="179.1" r=".25" fill="#008000"/>
<g fill="none" stroke="#008000" stroke-width=".13">
<path d="M14.4 177.8h15.1M15.7 177.8v3.8"/>
<circle cx="20.7" cy="179.1" r=".25"/>
</g>
<circle cx="15.7" cy="177.8" r=".25" fill="#008000"/>
<g fill="none" stroke="#008000" stroke-width=".13">
<path d="M62.2 137.6h-1.2v10.1h8.8M87.3 146.4h6.3v3.8"/>
<circle cx="15.7" cy="177.8" r=".25"/>
</g>
<circle cx="61" cy="147.7" r=".25" fill="#008000"/>
<g fill="none" stroke="#008000" stroke-width=".13">
<path d="M49.7 146.4v3.8M54.7 146.4h15.1M55.9 146.4v3.8"/>
<circle cx="61" cy="147.7" r=".25"/>
</g>
<circle cx="55.9" cy="146.4" r=".25" fill="#008000"/>
<g fill="none" stroke="#008000" stroke-width=".13">
<path d="M89.9 131.3v16.4h-2.6"/>
<circle cx="55.9" cy="146.4" r=".25"/>
</g>
<circle cx="89.9" cy="141.4" r=".25" fill="#008000"/>
<g fill="none" stroke="#008000" stroke-width=".13">
<path d="M89.9 141.4h8.8v8.8"/>
<circle cx="89.9" cy="141.4" r=".25"/>
</g>
<circle cx="98.7" cy="141.4" r=".25" fill="#008000"/>
<g fill="none" stroke="#008000" stroke-width=".13">
<path d="M89.9 131.3h11.9M88.6 147.7v2.5"/>
<circle cx="98.7" cy="141.4" r=".25"/>
</g>
<circle cx="88.6" cy="147.7" r=".25" fill="#008000"/>
<g fill="none" stroke="#008000" stroke-width=".13">
<path d="M125.1 136.4h-3.8v2.5h139.5v37.7"/>
<circle cx="88.6" cy="147.7" r=".25"/>
</g>
<circle cx="125.1" cy="136.4" r=".25" fill="#008000"/>
<circle cx="125.1" cy="136.4" r=".25" fill="none" stroke="#008000" stroke-width=".13"/>
<circle cx="121.3" cy="136.4" r=".25" fill="#008000"/>
<g fill="none" stroke="#008000" stroke-width=".13">
<path d="M88.6 69.7h-1.3v5.1h36.5M108.7 69.7h1.3v5.1M231.9 176.6h28.9M231.9 179.1h13.8v12.5h-35.2v-8.8h-87.9v-2.5h1.2"/>
<circle cx="121.3" cy="136.4" r=".25"/>
</g>
<circle cx="110" cy="74.8" r=".25" fill="#008000"/>
<g fill="none" stroke="#008000" stroke-width=".13">
<path d="M123.8 67.2v7.6h130.7v80.4h-22.6"/>
<circle cx="110" cy="74.8" r=".25"/>
</g>
<circle cx="123.8" cy="74.8" r=".25" fill="#008000"/>
<g fill="none" stroke="#008000" stroke-width=".13">
<path d="M87.3 94.9v-5.1h23.9v10.1M88.6 97.4h-6.3v12.5M88.6 94.9h-8.8v13.8h-3.8M76 107.4v2.5"/>
<circle cx="123.8" cy="74.8" r=".25"/>
</g>
<circle cx="87.3" cy="94.9" r=".25" fill="#008000"/>
<circle cx="87.3" cy="94.9" r=".25" fill="none" stroke="#008000" stroke-width=".13"/>
<circle cx="76" cy="108.7" r=".25" fill="#008000"/>
<g fill="none" stroke="#008000" stroke-width=".13">
<path d="M108.7 99.9h2.5M108.7 97.4h8.8v5M76 115v3.7h41.5M108.7 102.4h3.8v16.3"/>
<circle cx="76" cy="108.7" r=".25"/>
</g>
<circle cx="112.5" cy="118.7" r=".25" fill="#008000"/>
<g fill="none" stroke="#008000" stroke-width=".13">
<path d="M108.7 94.9h3.8v7.5M117.5 107.4v11.3"/>
<circle cx="112.5" cy="118.7" r=".25"/>
</g>
<circle cx="112.5" cy="102.4" r=".25" fill="#008000"/>
<g fill="none" stroke="#008000" stroke-width=".13">
<path d="M117.5 118.7v1.3"/>
<circle cx="112.5" cy="102.4" r=".25"/>
</g>
<circle cx="117.5" cy="118.7" r=".25" fill="#008000"/>
<g fill="none" stroke="#008000" stroke-width=".13">
<path d="M82.3 115v3.7"/>
<circle cx="117.5" cy="118.7" r=".25"/>
</g>
<circle cx="82.3" cy="118.7" r=".25" fill="#008000"/>
<g fill="none" stroke="#008000" stroke-width=".13">
<path d="M76 79.8v3.8h41.5M108.7 67.2h3.8v16.4"/>
<circle cx="82.3" cy="118.7" r=".25"/>
</g>
<circle cx="112.5" cy="83.6" r=".25" fill="#008000"/>
<g fill="none" stroke="#008000" stroke-width=".13">
<path d="M108.7 59.7h3.8v7.5M117.5 72.3v11.3"/>
<circle cx="112.5" cy="83.6" r=".25"/>
</g>
<circle cx="112.5" cy="67.2" r=".25" fill="#008000"/>
<g fill="none" stroke="#008000" stroke-width=".13">
<path d="M117.5 83.6v2.5"/>
<circle cx="112.5" cy="67.2" r=".25"/>
</g>
<circle cx="117.5" cy="83.6" r=".25" fill="#008000"/>
<g fill="none" stroke="#008000" stroke-width=".13">
<path d="M82.3 79.8v3.8"/>
<circle cx="117.5" cy="83.6" r=".25"/>
</g>
<circle cx="82.3" cy="83.6" r=".25" fill="#008000"/>
<g fill="none" stroke="#008000" stroke-width=".13">
<path d="M177.8 61v5h-11.3v-1.3M219.3 97.4h1.9"/>
<circle cx="82.3" cy="83.6" r=".25"/>
</g>
<circle cx="177.8" cy="66" r=".25" fill="#008000"/>
<g fill="none" stroke="#008000" stroke-width=".13">
<path d="M177.8 66h88.1v94.2h-34M220.6 66v31.4"/>
<circle cx="177.8" cy="66" r=".25"/>
</g>
<circle cx="220.6" cy="66" r=".25" fill="#008000"/>
<circle cx="220.6" cy="66" r=".25" fill="none" stroke="#008000" stroke-width=".13"/>
<circle cx="220.6" cy="97.4" r=".25" fill="#008000"/>
<g fill="none" stroke="#008000" stroke-width=".13">
<path d="M177.8 28.3v5h-11.3v-1.3"/>
<circle cx="220.6" cy="97.4" r=".25"/>
</g>
<circle cx="177.8" cy="33.3" r=".25" fill="#008000"/>
<g fill="none" stroke="#008000" stroke-width=".13">
<path d="M177.8 33.3h42.8v32.7M199.2 22h2.5v11.3"/>
<circle cx="177.8" cy="33.3" r=".25"/>
</g>
<circle cx="201.7" cy="33.3" r=".25" fill="#008000"/>
<g fill="none" stroke="#008000" stroke-width=".13">
<path d="M199.2 54.7h2.5v11.3"/>
<circle cx="201.7" cy="33.3" r=".25"/>
</g>
<circle cx="201.7" cy="66" r=".25" fill="#008000"/>
<g fill="none" stroke="#008000" stroke-width=".13">
<path d="M151.5 50.9v15.1h15"/>
<circle cx="201.7" cy="66" r=".25"/>
</g>
<circle cx="166.5" cy="66" r=".25" fill="#008000"/>
<g fill="none" stroke="#008000" stroke-width=".13">
<path d="M151.5 18.2v15.1h15"/>
<circle cx="166.5" cy="66" r=".25"/>
</g>
<circle cx="166.5" cy="33.3" r=".25" fill="#008000"/>
<g fill="none" stroke="#008000" stroke-width=".13">
<path d="M214.9 98.6h6.3M220.6 97.4v10h.6M20.7 184.1v2.5M59.7 186.6v2.5M72.3 181.6v5h-62.9"/>
<circle cx="166.5" cy="33.3" r=".25"/>
</g>
<circle cx="20.7" cy="186.6" r=".25" fill="#008000"/>
<circle cx="20.7" cy="186.6" r=".25" fill="none" stroke="#008000" stroke-width=".13"/>
<circle cx="25.7" cy="186.6" r=".25" fill="#008000"/>
<g fill="none" stroke="#008000" stroke-width=".13">
<path d="M25.7 180.3v6.3M53.4 185.4v1.2"/>
<circle cx="25.7" cy="186.6" r=".25"/>
</g>
<circle cx="53.4" cy="186.6" r=".25" fill="#008000"/>
<circle cx="53.4" cy="186.6" r=".25" fill="none" stroke="#008000" stroke-width=".13"/>
<circle cx="59.7" cy="186.6" r=".25" fill="#008000"/>
<g fill="none" stroke="#008000" stroke-width=".13">
<path d="M67.2 180.3v6.3"/>
<circle cx="59.7" cy="186.6" r=".25"/>
</g>
<circle cx="67.2" cy="186.6" r=".25" fill="#008000"/>
<circle cx="67.2" cy="186.6" r=".25" fill="none" stroke="#008000" stroke-width=".13"/>
<circle cx="72.3" cy="186.6" r=".25" fill="#008000"/>
<g fill="none" stroke="#008000" stroke-width=".13">
<path d="M72.3 186.6h76.6v3.8"/>
<circle cx="72.3" cy="186.6" r=".25"/>
</g>
<circle cx="148.9" cy="186.6" r=".25" fill="#008000"/>
<g fill="none" stroke="#008000" stroke-width=".13">
<path d="M148.9 190.4v3.7"/>
<circle cx="148.9" cy="186.6" r=".25"/>
</g>
<circle cx="148.9" cy="190.4" r=".25" fill="#008000"/>
<g fill="none" stroke="#008000" stroke-width=".13">
<path d="M9.4 185.4v1.2M15.7 185.4v1.2"/>
<circle cx="148.9" cy="190.4" r=".25"/>
</g>
<circle cx="15.7" cy="186.6" r=".25" fill="#008000"/>
<g fill="none" stroke="#008000" stroke-width=".13">
<path d="M221.2 118.7h-11.9v15.1h-5v56.6h-55.4M220.6 156.5h-15.1v37.6h-56.6M48.4 185.4v1.2M148.9 186.6h35.2"/>
<circle cx="15.7" cy="186.6" r=".25"/>
</g>
<circle cx="48.4" cy="186.6" r=".25" fill="#008000"/>
<g fill="none" stroke="#008000" stroke-width=".13">
<path d="M58.4 185.4v1.2"/>
<circle cx="48.4" cy="186.6" r=".25"/>
</g>
<circle cx="58.4" cy="186.6" r=".25" fill="#008000"/>
<g fill="none" stroke="#008000" stroke-width=".13">
<path d="M182.9 150.2h2.5M184.1 150.2v5M25.7 180.3h3.8"/>
<circle cx="58.4" cy="186.6" r=".25"/>
</g>
<circle cx="184.2" cy="150.2" r=".25" fill="#008000"/>
<g fill="none" stroke="#008000" stroke-width=".13">
<path d="M164 145.2v10h20.1v31.4"/>
<circle cx="184.2" cy="150.2" r=".25"/>
</g>
<circle cx="184.2" cy="155.2" r=".25" fill="#008000"/>
<circle cx="184.2" cy="155.2" r=".25" fill="none" stroke="#008000" stroke-width=".13"/>
<circle cx="164" cy="147.7" r=".25" fill="#008000"/>
<g fill="none" stroke="#008000" stroke-width=".13">
<path d="M164 147.7h1.3M164 145.2h1.3M123.8 177.8h-3.8v8.8"/>
<circle cx="164" cy="147.7" r=".25"/>
</g>
<circle cx="120" cy="186.6" r=".25" fill="#008000"/>
<g fill="none" stroke="#008000" stroke-width=".13">
<path d="M94.9 184.1h-2.5v2.5"/>
<circle cx="120" cy="186.6" r=".25"/>
</g>
<circle cx="92.4" cy="186.6" r=".25" fill="#008000"/>
<g fill="none" stroke="#008000" stroke-width=".13">
<path d="M81.1 167.8h-2.6v18.8"/>
<circle cx="92.4" cy="186.6" r=".25"/>
</g>
<circle cx="78.5" cy="186.6" r=".25" fill="#008000"/>
<circle cx="78.5" cy="186.6" r=".25" fill="none" stroke="#008000" stroke-width=".13"/>
<circle cx="87.3" cy="186.6" r=".25" fill="#008000"/>
<g fill="none" stroke="#008000" stroke-width=".13">
<path d="M81.1 185.4v1.2M107.4 184.1h2.6v2.5"/>
<circle cx="87.3" cy="186.6" r=".25"/>
</g>
<circle cx="110" cy="186.6" r=".25" fill="#008000"/>
<g fill="none" stroke="#008000" stroke-width=".13">
<path d="M61 152.7v2.5M112.5 150.2v5h-62.8"/>
<circle cx="110" cy="186.6" r=".25"/>
</g>
<circle cx="61" cy="155.2" r=".25" fill="#008000"/>
<g fill="none" stroke="#008000" stroke-width=".13">
<path d="M66 145.2v3.7"/>
<circle cx="61" cy="155.2" r=".25"/>
</g>
<circle cx="66" cy="155.2" r=".25" fill="#008000"/>
<g fill="none" stroke="#008000" stroke-width=".13">
<path d="M66 148.9v6.3M93.6 153.9v1.3"/>
<circle cx="66" cy="155.2" r=".25"/>
</g>
<circle cx="93.6" cy="155.2" r=".25" fill="#008000"/>
<g fill="none" stroke="#008000" stroke-width=".13">
<path d="M107.4 148.9v6.3"/>
<circle cx="93.6" cy="155.2" r=".25"/>
</g>
<circle cx="107.4" cy="155.2" r=".25" fill="#008000"/>
<g fill="none" stroke="#008000" stroke-width=".13">
<path d="M49.7 153.9v1.3M55.9 153.9v1.3"/>
<circle cx="107.4" cy="155.2" r=".25"/>
</g>
<circle cx="55.9" cy="155.2" r=".25" fill="#008000"/>
<g fill="none" stroke="#008000" stroke-width=".13">
<path d="M88.6 153.9v1.3"/>
<circle cx="55.9" cy="155.2" r=".25"/>
</g>
<circle cx="88.6" cy="155.2" r=".25" fill="#008000"/>
<g fill="none" stroke="#008000" stroke-width=".13">
<path d="M98.7 153.9v1.3"/>
<circle cx="88.6" cy="155.2" r=".25"/>
</g>
<circle cx="98.7" cy="155.2" r=".25" fill="#008000"/>
<g fill="none" stroke="#008000" stroke-width=".13">
<path d="M66 145.2h3.8M66 148.9h3.8"/>
<circle cx="98.7" cy="155.2" r=".25"/>
</g>
<circle cx="66" cy="148.9" r=".25" fill="#008000"/>
<circle cx="66" cy="148.9" r=".25" fill="none" stroke="#008000" stroke-width=".13"/>
<circle cx="84.8" cy="155.2" r=".25" fill="#008000"/>
<g fill="none" stroke="#008000" stroke-width=".13">
<path d="M96.1 20.7h2.6M96.1 25.7h2.6M96.1 28.3h2.6M120 20.7h1.3v-3.8h-25.2v30.2h-8.8v-6.2M91.1 40.9v6.2"/>
<circle cx="84.8" cy="155.2" r=".25"/>
</g>
<circle cx="96.1" cy="47.1" r=".25" fill="#008000"/>
<circle cx="96.1" cy="47.1" r=".25" fill="none" stroke="#008000" stroke-width=".13"/>
<circle cx="91.1" cy="47.1" r=".25" fill="#008000"/>
<circle cx="91.1" cy="47.1" r=".25" fill="none" stroke="#008000" stroke-width=".13"/>
<circle cx="96.1" cy="20.7" r=".25" fill="#008000"/>
<circle cx="96.1" cy="20.7" r=".25" fill="none" stroke="#008000" stroke-width=".13"/>
<circle cx="96.1" cy="25.7" r=".25" fill="#008000"/>
<circle cx="96.1" cy="25.7" r=".25" fill="none" stroke="#008000" stroke-width=".13"/>
<circle cx="96.1" cy="28.3" r=".25" fill="#008000"/>
<g fill="none" stroke="#008000" stroke-width=".13">
<path d="M120 30.8h8.8v2.5M128.8 28.3h3.8v18.8h-36.5"/>
<circle cx="96.1" cy="28.3" r=".25"/>
</g>
<circle cx="128.8" cy="47.1" r=".25" fill="#008000"/>
<g fill="none" stroke="#008000" stroke-width=".13">
<path d="M120 33.3h8.8v13.8"/>
<circle cx="128.8" cy="47.1" r=".25"/>
</g>
<circle cx="128.8" cy="33.3" r=".25" fill="#008000"/>
<g fill="none" stroke="#008000" stroke-width=".13">
<path d="M87.3 47.1v2.5"/>
<circle cx="128.8" cy="33.3" r=".25"/>
</g>
<circle cx="87.3" cy="47.1" r=".25" fill="#008000"/>
<g fill="none" stroke="#008000" stroke-width=".13">
<path d="M123.8 47.1v7.6"/>
<circle cx="87.3" cy="47.1" r=".25"/>
</g>
<circle cx="123.8" cy="47.1" r=".25" fill="#008000"/>
<g fill="none" stroke="#008000" stroke-width=".13">
<path d="M98.7 40.9v6.2M128.8 47.1v7.6"/>
<circle cx="123.8" cy="47.1" r=".25"/>
</g>
<circle cx="98.7" cy="43.4" r=".25" fill="#008000"/>
<circle cx="98.7" cy="43.4" r=".25" fill="none" stroke="#008000" stroke-width=".13"/>
<circle cx="98.7" cy="47.1" r=".25" fill="#008000"/>
<g fill="none" stroke="#008000" stroke-width=".13">
<path d="M98.7 38.3v2.6"/>
<circle cx="98.7" cy="47.1" r=".25"/>
</g>
<circle cx="98.7" cy="40.9" r=".25" fill="#008000"/>
<g fill="none" stroke="#008000" stroke-width=".13">
<path d="M98.7 35.8v2.5M220.6 177.8h-8.2v10.1M212.4 185.4h8.2M212.4 182.8h8.2M212.4 180.3h8.2"/>
<circle cx="98.7" cy="40.9" r=".25"/>
</g>
<circle cx="212.4" cy="180.3" r=".25" fill="#008000"/>
<circle cx="212.4" cy="180.3" r=".25" fill="none" stroke="#008000" stroke-width=".13"/>
<circle cx="212.4" cy="182.8" r=".25" fill="#008000"/>
<circle cx="212.4" cy="182.8" r=".25" fill="none" stroke="#008000" stroke-width=".13"/>
<circle cx="212.4" cy="185.4" r=".25" fill="#008000"/>
<g fill="none" stroke="#008000" stroke-width=".13">
<path d="M87.3 59.7v-5h23.9v10M88.6 59.7h-8.8v13.8h-3.8M76 72.3v2.5M88.6 62.2h-6.3v12.6"/>
<circle cx="212.4" cy="185.4" r=".25"/>
</g>
<circle cx="87.3" cy="59.7" r=".25" fill="#008000"/>
<circle cx="87.3" cy="59.7" r=".25" fill="none" stroke="#008000" stroke-width=".13"/>
<circle cx="76" cy="73.5" r=".25" fill="#008000"/>
<g fill="none" stroke="#008000" stroke-width=".13">
<path d="M108.7 64.7h2.5M108.7 62.2h8.8v5M88.6 104.9h-1.3v5h41.5M108.7 104.9h1.3v5"/>
<circle cx="76" cy="73.5" r=".25"/>
</g>
<circle cx="110" cy="109.9" r=".25" fill="#008000"/>
<g fill="none" stroke="#008000" stroke-width=".13">
<path d="M128.8 67.2v42.7h23.9v-2.5h57.8v60.4h6.3v5h3.8"/>
<circle cx="110" cy="109.9" r=".25"/>
</g>
<circle cx="128.8" cy="109.9" r=".25" fill="#008000"/>
<g fill="none" stroke="#008000" stroke-width=".13">
<path d="M220.6 155.2h-18.9v11.3h-66.6v-10h5M9.4 177.8v3.8M47.1 176.6h20.1M66 172.8h1.2v5"/>
<circle cx="128.8" cy="109.9" r=".25"/>
</g>
<circle cx="67.2" cy="176.6" r=".25" fill="#008000"/>
<g fill="none" stroke="#008000" stroke-width=".13">
<path d="M67.2 172.8h.7"/>
<circle cx="67.2" cy="176.6" r=".25"/>
</g>
<circle cx="67.2" cy="172.8" r=".25" fill="#008000"/>
<g fill="none" stroke="#008000" stroke-width=".13">
<path d="M87.3 145.2h20.1M107.4 141.4v5"/>
<circle cx="67.2" cy="172.8" r=".25"/>
</g>
<circle cx="107.4" cy="145.2" r=".25" fill="#008000"/>
<g fill="none" stroke="#008000" stroke-width=".13">
<path d="M106.2 141.4h1.9"/>
<circle cx="107.4" cy="145.2" r=".25"/>
</g>
<circle cx="107.4" cy="141.4" r=".25" fill="#008000"/>
<g fill="none" stroke="#008000" stroke-width=".13">
<path d="M112.5 141.4v5"/>
<circle cx="107.4" cy="141.4" r=".25"/>
</g>
<circle cx="112.5" cy="141.4" r=".25" fill="#008000"/>
<g fill="none" stroke="#008000" stroke-width=".13">
<path d="M67.2 137.6h45.3v3.8M111.8 141.4h146.5v26.4h-26.4M240.7 167.8v1.2h-8.8"/>
<circle cx="112.5" cy="141.4" r=".25"/>
</g>
<circle cx="240.7" cy="167.8" r=".25" fill="#008000"/>
<g fill="none" stroke="#008000" stroke-width=".13">
<path d="M231.9 171.5h21.4M231.9 170.3h21.4v23.8h-45.3v-21.3h-85.4"/>
<circle cx="240.7" cy="167.8" r=".25"/>
</g>
<circle cx="253.3" cy="171.5" r=".25" fill="#008000"/>
<g fill="none" stroke="#008000" stroke-width=".13">
<path d="M160.2 45.8v-2.5h28.9v2.5M166.5 43.3v2.5"/>
<circle cx="253.3" cy="171.5" r=".25"/>
</g>
<circle cx="166.5" cy="43.4" r=".25" fill="#008000"/>
<circle cx="166.5" cy="43.4" r=".25" fill="none" stroke="#008000" stroke-width=".13"/>
<circle cx="189.1" cy="43.4" r=".25" fill="#008000"/>
<g fill="none" stroke="#008000" stroke-width=".13">
<path d="M177.8 43.3v5.1"/>
<circle cx="189.1" cy="43.4" r=".25"/>
</g>
<circle cx="177.8" cy="43.4" r=".25" fill="#008000"/>
<g fill="none" stroke="#008000" stroke-width=".13">
<path d="M160.2 13.2v-2.5h28.9v2.5M166.5 10.7v2.5M189.1 43.3h80.5v128.2h-16.3M122.6 172.8v2.5h1.2"/>
<circle cx="177.8" cy="43.4" r=".25"/>
</g>
<circle cx="166.5" cy="10.7" r=".25" fill="#008000"/>
<circle cx="166.5" cy="10.7" r=".25" fill="none" stroke="#008000" stroke-width=".13"/>
<circle cx="189.1" cy="10.7" r=".25" fill="#008000"/>
<g fill="none" stroke="#008000" stroke-width=".13">
<path d="M177.8 10.7v5"/>
<circle cx="189.1" cy="10.7" r=".25"/>
</g>
<circle cx="177.8" cy="10.7" r=".25" fill="#008000"/>
<g fill="none" stroke="#008000" stroke-width=".13">
<path d="M189.1 10.7h80.5v32.6"/>
<circle cx="177.8" cy="10.7" r=".25"/>
</g>
<circle cx="269.6" cy="43.4" r=".25" fill="#008000"/>
<g fill="none" stroke="#008000" stroke-width=".13">
<path d="M160.2 43.3h-8.7v3.8"/>
<circle cx="269.6" cy="43.4" r=".25"/>
</g>
<circle cx="160.2" cy="43.4" r=".25" fill="#008000"/>
<g fill="none" stroke="#008000" stroke-width=".13">
<path d="M160.2 10.7h-8.7v3.7"/>
<circle cx="160.2" cy="43.4" r=".25"/>
</g>
<circle cx="160.2" cy="10.7" r=".25" fill="#008000"/>
<g fill="none" stroke="#008000" stroke-width=".13">
<path d="M113.7 172.8h8.9"/>
<circle cx="160.2" cy="10.7" r=".25"/>
</g>
<circle cx="122.6" cy="172.8" r=".25" fill="#008000"/>
<g fill="none" stroke="#008000" stroke-width=".13">
<path d="M113.7 172.8v7.5h-6.3"/>
<circle cx="122.6" cy="172.8" r=".25"/>
</g>
<circle cx="113.8" cy="172.8" r=".25" fill="#008000"/>
<g fill="none" stroke="#008000" stroke-width=".13">
<path d="M221.2 106.2h-9.4v67.8M211.8 148.9h40.2v23.9"/>
<circle cx="113.8" cy="172.8" r=".25"/>
</g>
<circle cx="211.8" cy="148.9" r=".25" fill="#008000"/>
<g fill="none" stroke="#008000" stroke-width=".13">
<path d="M220.6 174h-8.8v1.3h8.8"/>
<circle cx="211.8" cy="148.9" r=".25"/>
</g>
<circle cx="211.8" cy="174" r=".25" fill="#008000"/>
<g fill="none" stroke="#008000" stroke-width=".13">
<path d="M142.7 161.5h66.6v31.4h37.7v-15.1h-15.1M231.9 172.8h20.1"/>
<circle cx="211.8" cy="174" r=".25"/>
</g>
<circle cx="148.9" cy="161.5" r=".25" fill="#008000"/>
<g fill="none" stroke="#008000" stroke-width=".13">
<path d="M105.6 131.3h13.2M87.3 148.9h15.1M182.9 145.2h16.3v3.7M198 147.7h1.2"/>
<circle cx="148.9" cy="161.5" r=".25"/>
</g>
<circle cx="199.2" cy="147.7" r=".25" fill="#008000"/>
<g fill="none" stroke="#008000" stroke-width=".13">
<path d="M182.9 147.7h11.3v1.2"/>
<circle cx="199.2" cy="147.7" r=".25"/>
</g>
<circle cx="194.2" cy="147.7" r=".25" fill="#008000"/>
<g fill="none" stroke="#008000" stroke-width=".13">
<path d="M120 25.7h20.1v110.7h110.6v-39M162.8 136.4v13.8h2.5"/>
<circle cx="194.2" cy="147.7" r=".25"/>
</g>
<circle cx="162.8" cy="136.4" r=".25" fill="#008000"/>
<g fill="none" stroke="#008000" stroke-width=".13">
<path d="M120 23.2h21.4v111.9h108.1v-36.5M232.5 97.4h18.2M161.5 135.1v17.6h3.8"/>
<circle cx="162.8" cy="136.4" r=".25"/>
</g>
<circle cx="161.5" cy="135.1" r=".25" fill="#008000"/>
<g fill="none" stroke="#008000" stroke-width=".13">
<path d="M232.5 98.6h17M231.9 166.5h22.6v28.9h-47.7v-20.1"/>
<circle cx="161.5" cy="135.1" r=".25"/>
</g>
<circle cx="254.5" cy="166.5" r=".25" fill="#008000"/>
<g fill="none" stroke="#008000" stroke-width=".13">
<path d="M160.2 50.9v18.8M160.2 52.2h11.4M263.3 69.7v89.3h-31.4M136.4 175.3h70.4M231.9 164h22.6v2.5"/>
<circle cx="254.5" cy="166.5" r=".25"/>
</g>
<circle cx="160.2" cy="52.2" r=".25" fill="#008000"/>
<g fill="none" stroke="#008000" stroke-width=".13">
<path d="M120 38.3h15.1v13.9h25.1M186.6 54.7h7.6M189.1 50.9v3.8M160.2 69.7h103.1"/>
<circle cx="160.2" cy="52.2" r=".25"/>
</g>
<circle cx="189.1" cy="54.7" r=".25" fill="#008000"/>
<g fill="none" stroke="#008000" stroke-width=".13">
<path d="M166.5 50.9v8.8M166.5 57.1h5.1"/>
<circle cx="189.1" cy="54.7" r=".25"/>
</g>
<circle cx="166.5" cy="57.2" r=".25" fill="#008000"/>
<g fill="none" stroke="#008000" stroke-width=".13">
<path d="M199.2 19.5h69.2v138.2h-36.5M199.2 52.2h69.2"/>
<circle cx="166.5" cy="57.2" r=".25"/>
</g>
<circle cx="268.4" cy="52.2" r=".25" fill="#008000"/>
<g fill="none" stroke="#008000" stroke-width=".13">
<path d="M189.1 18.2v3.8M186.6 22h7.6"/>
<circle cx="268.4" cy="52.2" r=".25"/>
</g>
<circle cx="189.1" cy="22" r=".25" fill="#008000"/>
<g fill="none" stroke="#008000" stroke-width=".13">
<path d="M166.5 18.2v8.8M166.5 24.5h5.1"/>
<circle cx="189.1" cy="22" r=".25"/>
</g>
<circle cx="166.5" cy="24.5" r=".25" fill="#008000"/>
<g fill="none" stroke="#008000" stroke-width=".13">
<path d="M160.2 18.2v18.8M160.2 19.5h11.4M272.1 37v124.5h-40.2"/>
<circle cx="166.5" cy="24.5" r=".25"/>
</g>
<circle cx="160.2" cy="19.5" r=".25" fill="#008000"/>
<g fill="none" stroke="#008000" stroke-width=".13">
<path d="M160.2 19.5h-13.8v16.3h-26.4M160.2 37h111.9M199.2 153.9v2.6M200.5 170.3h12.5v6.3h7.6"/>
<circle cx="160.2" cy="19.5" r=".25"/>
</g>
<circle cx="199.2" cy="156.5" r=".25" fill="#008000"/>
<g fill="none" stroke="#008000" stroke-width=".13">
<path d="M206.8 120.6v10.7h-5.1v11.3h-1.2v27.7M199.2 156.5h1.3"/>
<circle cx="199.2" cy="156.5" r=".25"/>
</g>
<circle cx="200.5" cy="156.5" r=".25" fill="#008000"/>
<g fill="none" stroke="#008000" stroke-width=".13">
<path d="M120 28.3h3.8M123.8 59.7v2.5M121.3 61h2.5M232.5 118.7h.7v1.9h-26.4"/>
<circle cx="200.5" cy="156.5" r=".25"/>
</g>
<circle cx="123.8" cy="61" r=".25" fill="#008000"/>
<g fill="none" stroke="#008000" stroke-width=".13">
<path d="M120 43.3h1.3v17.7M126.3 40.9v20.1h2.5M128.8 59.7v2.5"/>
<circle cx="123.8" cy="61" r=".25"/>
</g>
<circle cx="128.8" cy="61" r=".25" fill="#008000"/>
<g fill="none" stroke="#008000" stroke-width=".13">
<path d="M120 40.9h6.3M81.1 174h11.3v6.3h2.5M93.6 165.3h1.3v13.8"/>
<circle cx="128.8" cy="61" r=".25"/>
</g>
<circle cx="87.3" cy="174" r=".25" fill="#008000"/>
<circle cx="87.3" cy="174" r=".25" fill="none" stroke="#008000" stroke-width=".13"/>
<circle cx="81.1" cy="174" r=".25" fill="#008000"/>
<g fill="none" stroke="#008000" stroke-width=".13">
<path d="M87.3 179.1v2.5h2.6v1.2h5"/>
<circle cx="81.1" cy="174" r=".25"/>
</g>
<circle cx="87.3" cy="181.6" r=".25" fill="#008000"/>
<g fill="none" stroke="#008000" stroke-width=".13">
<path d="M81.1 180.3v-1.2h10v2.5h3.8"/>
<circle cx="87.3" cy="181.6" r=".25"/>
</g>
<circle cx="81.1" cy="179.1" r=".25" fill="#008000"/>
<g fill="none" stroke="#008000" stroke-width=".13">
<path d="M25.7 176.6h3.8M47.1 177.8h6.3v3.8M58.4 172.8v8.8"/>
<circle cx="81.1" cy="179.1" r=".25"/>
</g>
<circle cx="58.4" cy="172.8" r=".25" fill="#008000"/>
<g fill="none" stroke="#008000" stroke-width=".13">
<path d="M49.7 172.8v6.3h-2.6"/>
<circle cx="58.4" cy="172.8" r=".25"/>
</g>
<circle cx="49.7" cy="172.8" r=".25" fill="#008000"/>
<g fill="none" stroke="#008000" stroke-width=".13">
<path d="M48.4 179.1v2.5M49.7 172.8h8.7"/>
<circle cx="49.7" cy="172.8" r=".25"/>
</g>
<circle cx="48.4" cy="179.1" r=".25" fill="#008000"/>
<g fill="none" stroke="#008000" stroke-width=".13">
<path d="M59.1 162.7h-9.4v10.1h-24v3.8M62.8 162.7h49.7M118.8 167.8h-3.8v15h-7.6"/>
<circle cx="48.4" cy="179.1" r=".25"/>
</g>
<circle cx="115" cy="167.8" r=".25" fill="#008000"/>
<g fill="none" stroke="#008000" stroke-width=".13">
<path d="M91.1 33.3v3.7"/>
<circle cx="115" cy="167.8" r=".25"/>
</g>
<circle cx="91.1" cy="33.3" r=".25" fill="#008000"/>
<g fill="none" stroke="#008000" stroke-width=".13">
<path d="M93.6 33.3h5.1"/>
<circle cx="91.1" cy="33.3" r=".25"/>
</g>
<circle cx="93.6" cy="33.3" r=".25" fill="#008000"/>
<g fill="none" stroke="#008000" stroke-width=".13">
<path d="M93.6 30.8h5.1"/>
<circle cx="93.6" cy="33.3" r=".25"/>
</g>
<circle cx="93.6" cy="30.8" r=".25" fill="#008000"/>
<g fill="none" stroke="#008000" stroke-width=".13">
<path d="M87.3 37v-3.7h6.3v-18.9h50.3v105.6h46.5M93.6 23.2h5.1M232.5 108.7h15.7v28.9h-57.8v12.6h-1.3v2.5h-6.2"/>
<circle cx="93.6" cy="30.8" r=".25"/>
</g>
<circle cx="189.1" cy="150.2" r=".25" fill="#008000"/>
<g fill="none" stroke="#008000" stroke-width=".13">
<path d="M190.4 120v17.6"/>
<circle cx="189.1" cy="150.2" r=".25"/>
</g>
<circle cx="190.4" cy="137.6" r=".25" fill="#008000"/>
<g fill="none" stroke="#008000" stroke-width=".13">
<path d="M143.9 120v27h-12.5v22h-13.9v6.3"/>
<circle cx="190.4" cy="137.6" r=".25"/>
</g>
<circle cx="143.9" cy="120" r=".25" fill="#008000"/>
<g fill="none" stroke="#008000" stroke-width=".13">
<path d="M108.7 172.8v6.3h-1.3"/>
<circle cx="143.9" cy="120" r=".25"/>
</g>
<circle cx="108.7" cy="172.8" r=".25" fill="#008000"/>
<g fill="none" stroke="#008000" stroke-width=".13">
<path d="M72.3 172.8v5"/>
<circle cx="108.7" cy="172.8" r=".25"/>
</g>
<circle cx="72.3" cy="172.8" r=".25" fill="#008000"/>
<g fill="none" stroke="#008000" stroke-width=".13">
<path d="M88.6 64.7h-2.5v2.5h2.5M231.9 156.5h17.6v-5.1h-46.5v7.6h-13.9M27 169h45.3v3.8M71.6 172.8h37.1M77.3 165.3h3.8M118.8 160.2h-41.5v10.1h3.8"/>
<circle cx="72.3" cy="172.8" r=".25"/>
</g>
<circle cx="86.1" cy="67.2" r=".25" fill="#008000"/>
<g fill="none" stroke="#008000" stroke-width=".13">
<path d="M76 67.2h10.1"/>
<circle cx="86.1" cy="67.2" r=".25"/>
</g>
<circle cx="76" cy="67.2" r=".25" fill="#008000"/>
<g fill="none" stroke="#008000" stroke-width=".13">
<path d="M76 67.2h-7.5v35.2"/>
<circle cx="76" cy="67.2" r=".25"/>
</g>
<circle cx="68.5" cy="102.4" r=".25" fill="#008000"/>
<g fill="none" stroke="#008000" stroke-width=".13">
<path d="M88.6 99.9h-2.5v2.5h2.5M68.5 102.4v20.1"/>
<circle cx="68.5" cy="102.4" r=".25"/>
</g>
<circle cx="86.1" cy="102.4" r=".25" fill="#008000"/>
<g fill="none" stroke="#008000" stroke-width=".13">
<path d="M68.5 102.4h17.6"/>
<circle cx="86.1" cy="102.4" r=".25"/>
</g>
<circle cx="76" cy="102.4" r=".25" fill="#008000"/>
<circle cx="76" cy="102.4" r=".25" fill="none" stroke="#008000" stroke-width=".13"/>
<circle cx="148.9" cy="125.1" r=".25" fill="#008000"/>
<g fill="none" stroke="#008000" stroke-width=".13">
<path d="M148.9 125.1h5.1v31.4h35.1"/>
<circle cx="148.9" cy="125.1" r=".25"/>
</g>
<circle cx="154" cy="156.5" r=".25" fill="#008000"/>
<g fill="none" stroke="#008000" stroke-width=".13">
<path d="M148.9 156.5h5.1M189.1 156.5h5.1"/>
<circle cx="154" cy="156.5" r=".25"/>
</g>
<circle cx="148.9" cy="156.5" r=".25" fill="#008000"/>
<g fill="none" stroke="#008000" stroke-width=".13">
<path d="M68.5 122.5h80.4v2.6M142.7 156.5h6.2M194.2 153.9v2.6"/>
<circle cx="148.9" cy="156.5" r=".25"/>
</g>
<circle cx="194.2" cy="156.5" r=".25" fill="#008000"/>
<g fill="none" stroke="#008000" stroke-width=".13">
<path d="M125.1 131.3h5M130.1 125.1v37.6h-15.1"/>
<circle cx="194.2" cy="156.5" r=".25"/>
</g>
<circle cx="130.1" cy="131.3" r=".25" fill="#008000"/>
<g fill="none" stroke="#008000" stroke-width=".13">
<path d="M121.3 131.3h3.8M130.1 125.1h18.8"/>
<circle cx="130.1" cy="131.3" r=".25"/>
</g>
<circle cx="125.1" cy="131.3" r=".25" fill="#008000"/>
<g fill="none" stroke="#008000" stroke-width=".13">
<path d="M189.1 156.5v2.5"/>
<circle cx="125.1" cy="131.3" r=".25"/>
</g>
<circle cx="189.1" cy="156.5" r=".25" fill="#008000"/>
<circle cx="189.1" cy="156.5" r=".25" fill="none" stroke="#008000" stroke-width=".13"/>
<circle cx="118.8" cy="162.7" r=".25" fill="#008000"/>
<g fill="none" stroke="#008000" stroke-width=".13">
<path d="M118.8 160.2v2.5"/>
<circle cx="118.8" cy="162.7" r=".25"/>
</g>
<circle cx="77.3" cy="165.3" r=".25" fill="#008000"/>
<g fill="none" stroke="#008000" stroke-width=".13">
<path d="M117.5 180.3v1.3h-10.1"/>
<circle cx="77.3" cy="165.3" r=".25"/>
</g>
<circle cx="117.5" cy="181.6" r=".25" fill="#008000"/>
<g fill="none" stroke="#008000" stroke-width=".13">
<path d="M117.5 181.6h3.8v16.9h138.9v-13.1h-28.3"/>
<circle cx="117.5" cy="181.6" r=".25"/>
</g>
<use href="#words"/>
</svg>
